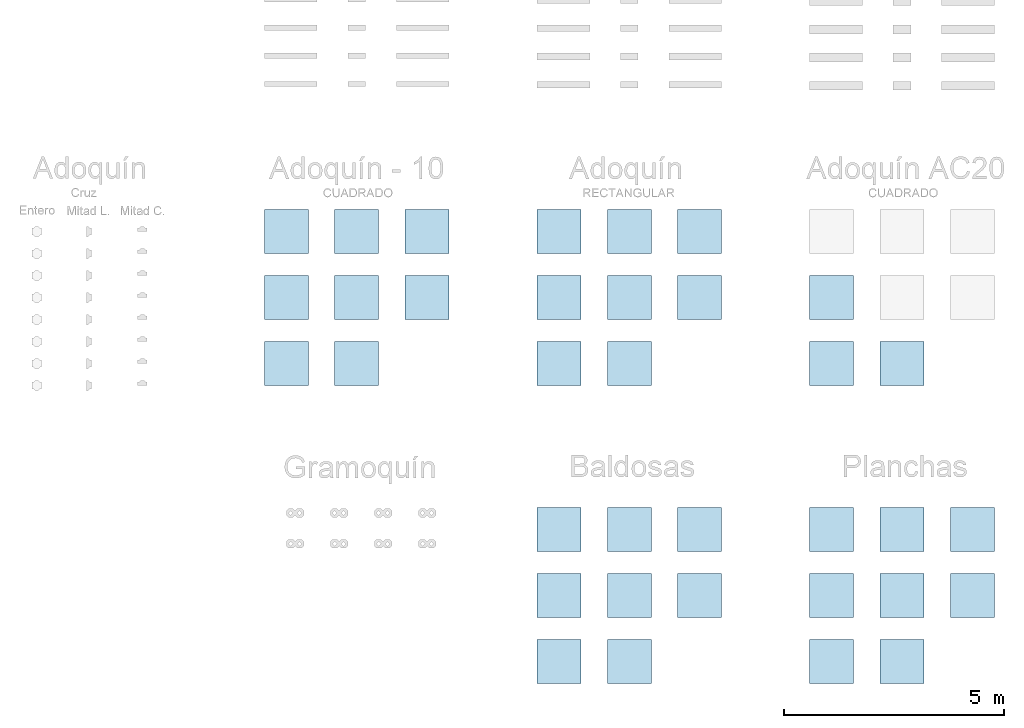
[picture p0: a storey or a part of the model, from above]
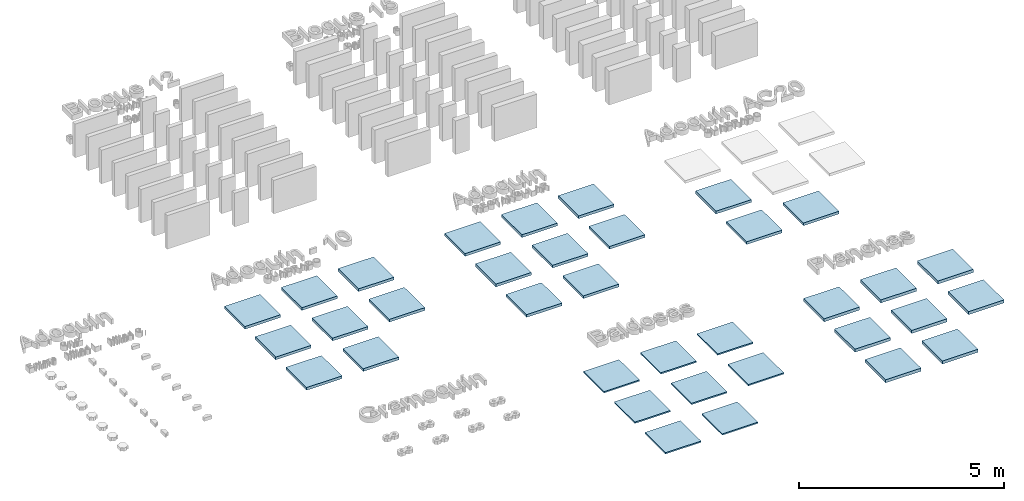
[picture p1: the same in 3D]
Properties of the parts of a building model (IFC2X3), part 1 of 2

# File
Description: ViewDefinition [CoordinationView_V2.0]
File name: Versión 1.0
Time: 2025-05-08T22:21:19
Written by: The EXPRESS Data Manager Version 5.02.0100.07 : 28 Aug 2013
Made in: 21.0.0.383 - Exporter 21.0.0.383 - IU alternativa 21.0.0.383
Comment: STEP Physical File produced by: The EXPRESS Data Manager Version 5.02.0100.07 : 28 Aug 2013 * Module: EDMstepFileFactory/EDMstandAlone * Creation date: Thu May 08 22:21:19 2025 * Host: MSI * Database: C:\Users\valem\AppData\Local\Temp\0c03b512-117e-4236-a8f6-5f3e5b4cf95f\990fe244-7826-4991-a4dd-d05e1d44d0d1\ifc * Database version: 5507 * Database creation date: Thu May 08 22:20:00 2025 * Schema: IFC2X3 * Model: DataRepository.ifc * Model creation date: Thu May 08 22:20:00 2025 * Header model: DataRepository.ifc_HeaderModel * Header model creation date: Thu May 08 22:20:00 2025 * EDMuser: sdai-user * EDMgroup: sdai-group * License ID and type: 5605 : Permanent license. Expiry date: * EDMstepFileFactory options: 020000

# IfcProject, Versión 1.0
LongName: Template Arquitectónicos de La Peña; Phase: Prototipo

# IfcSite, Default
RefLatitude: 40, 25, 13, 9643; RefLongitude: -3, -42, -20, -772056; RefElevation: 0 m

# IfcBuilding
Pset_BuildingCommon - NumberOfStoreys: 1

# IfcBuildingStorey: Nivel:Nivel 1, Nivel 1
LongName: Nivel 1; Elevation: 0 m

# IfcBuildingElementProxy: Texto de modelo:Subtítulo (19)
In: Nivel 1
Type - Pset_BuildingElementProxyCommon - Reference: Subtítulo
Type - Pset_QuantityTakeOff - Reference: Subtítulo
Pset_BuildingElementProxyCommon - sets with these values: 2
Pset_ProvisionForVoid - Shape: Undefined; Width: 0.15 m; Depth: 0.15 m
Name (Texto de modelo:Subtítulo:...)
163555
163556
163563 | Pset_ProvisionForVoid - Height: 0.200913 m
163564
163596
163597
163598 | Pset_ProvisionForVoid - Height: 0.200913 m
163599
163653
163654
163657 | Pset_ProvisionForVoid - Height: 0.200913 m
163658
163723
163767
163825
164239
164240
164241 | Pset_ProvisionForVoid - Height: 0.0251141 m
164242 | Pset_ProvisionForVoid - Height: 0.0251141 m

# IfcBuildingElementProxy: Texto de modelo:Título (10)
In: Nivel 1
Type - Pset_BuildingElementProxyCommon - Reference: Título
Type - Pset_QuantityTakeOff - Reference: Título
Pset_BuildingElementProxyCommon - sets with these values: 2
Pset_ProvisionForVoid - Shape: Undefined; Width: 0.15 m; Depth: 0.15 m
Name (Texto de modelo:Título:...) | Height (m)
163554 | 0.502282
163595 | 0.502282
163652 | 0.502282
163708 | 0.368863
163766 | 0.368863
163824 | 0.368863
163875 | 0.368863
164123 | 0.502282
164180 | 0.502282
164230 | 0.368863

# IfcSlab: Gramoquín10:Gramoquín, Gramoquín10:Gramoquín:164282
In: Nivel 1
Type - PredefinedType: FLOOR; Material: Adoquín Cruz - Rojo
Type - Pset_ManufacturerTypeInformation - Manufacturer: Bloques de la Peña
Type - Pset_QuantityTakeOff - Reference: Gramoquín
Type - Pset_ReinforcementBarPitchOfSlab - Reference: Gramoquín
Type - Pset_SlabCommon - IsExternal: no; Reference: Gramoquín
Pset_QuantityTakeOff - sets with these values: 2
Pset_SlabCommon - IsExternal: yes

# IfcSlab: Gramoquín11:Gramoquín, Gramoquín11:Gramoquín:164302
In: Nivel 1
Type - PredefinedType: FLOOR; Material: Adoquín Cruz - Adobe
Type - Pset_ManufacturerTypeInformation - Manufacturer: Bloques de la Peña
Type - Pset_QuantityTakeOff - Reference: Gramoquín
Type - Pset_ReinforcementBarPitchOfSlab - Reference: Gramoquín
Type - Pset_SlabCommon - IsExternal: no; Reference: Gramoquín
Pset_QuantityTakeOff - sets with these values: 2
Pset_SlabCommon - IsExternal: yes

# IfcSlab: Gramoquín12:Gramoquín, Gramoquín12:Gramoquín:164322
In: Nivel 1
Type - PredefinedType: FLOOR; Material: Adoquín Cruz - Amarillo
Type - Pset_ManufacturerTypeInformation - Manufacturer: Bloques de la Peña
Type - Pset_QuantityTakeOff - Reference: Gramoquín
Type - Pset_ReinforcementBarPitchOfSlab - Reference: Gramoquín
Type - Pset_SlabCommon - IsExternal: no; Reference: Gramoquín
Pset_QuantityTakeOff - sets with these values: 2
Pset_SlabCommon - IsExternal: yes

# IfcSlab: Gramoquín13:Gramoquín, Gramoquín13:Gramoquín:164342
In: Nivel 1
Type - PredefinedType: FLOOR; Material: Adoquín Cruz - Gris
Type - Pset_ManufacturerTypeInformation - Manufacturer: Bloques de la Peña
Type - Pset_QuantityTakeOff - Reference: Gramoquín
Type - Pset_ReinforcementBarPitchOfSlab - Reference: Gramoquín
Type - Pset_SlabCommon - IsExternal: no; Reference: Gramoquín
Pset_QuantityTakeOff - sets with these values: 2
Pset_SlabCommon - IsExternal: yes

# IfcSlab: Gramoquín14:Gramoquín, Gramoquín14:Gramoquín:164362
In: Nivel 1
Type - PredefinedType: FLOOR; Material: Adoquín Cruz - Chocolate
Type - Pset_ManufacturerTypeInformation - Manufacturer: Bloques de la Peña
Type - Pset_QuantityTakeOff - Reference: Gramoquín
Type - Pset_ReinforcementBarPitchOfSlab - Reference: Gramoquín
Type - Pset_SlabCommon - IsExternal: no; Reference: Gramoquín
Pset_QuantityTakeOff - sets with these values: 2
Pset_SlabCommon - IsExternal: yes

# IfcSlab: Gramoquín15:Gramoquín, Gramoquín15:Gramoquín:164382
In: Nivel 1
Type - PredefinedType: FLOOR; Material: Adoquín Cruz - Negro
Type - Pset_ManufacturerTypeInformation - Manufacturer: Bloques de la Peña
Type - Pset_QuantityTakeOff - Reference: Gramoquín
Type - Pset_ReinforcementBarPitchOfSlab - Reference: Gramoquín
Type - Pset_SlabCommon - IsExternal: no; Reference: Gramoquín
Pset_QuantityTakeOff - sets with these values: 2
Pset_SlabCommon - IsExternal: yes

# IfcSlab: Gramoquín16:Gramoquín, Gramoquín16:Gramoquín:164402
In: Nivel 1
Type - PredefinedType: FLOOR; Material: Adoquín Cruz - Natural
Type - Pset_ManufacturerTypeInformation - Manufacturer: Bloques de la Peña
Type - Pset_QuantityTakeOff - Reference: Gramoquín
Type - Pset_ReinforcementBarPitchOfSlab - Reference: Gramoquín
Type - Pset_SlabCommon - IsExternal: no; Reference: Gramoquín
Pset_QuantityTakeOff - sets with these values: 2
Pset_SlabCommon - IsExternal: yes

# IfcSlab: Gramoquín17:Gramoquín, Gramoquín17:Gramoquín:164433
In: Nivel 1
Type - PredefinedType: FLOOR; Material: Adoquín Cruz - Rosado
Type - Pset_ManufacturerTypeInformation - Manufacturer: Bloques de la Peña
Type - Pset_QuantityTakeOff - Reference: Gramoquín
Type - Pset_ReinforcementBarPitchOfSlab - Reference: Gramoquín
Type - Pset_SlabCommon - IsExternal: no; Reference: Gramoquín
Pset_QuantityTakeOff - sets with these values: 2
Pset_SlabCommon - IsExternal: yes

# IfcSlab: Gramoquín18:Gramoquín, Gramoquín18:Gramoquín:164449
In: Nivel 1
Type - PredefinedType: FLOOR; Material: Adoquín Cruz - Rojo
Type - Pset_ManufacturerTypeInformation - Manufacturer: Bloques de la Peña
Type - Pset_QuantityTakeOff - Reference: Gramoquín
Type - Pset_ReinforcementBarPitchOfSlab - Reference: Gramoquín
Type - Pset_SlabCommon - IsExternal: no; Reference: Gramoquín
Pset_QuantityTakeOff - sets with these values: 2
Pset_SlabCommon - IsExternal: yes

# IfcSlab: Gramoquín19:Gramoquín, Gramoquín19:Gramoquín:164465
In: Nivel 1
Type - PredefinedType: FLOOR; Material: Adoquín Cruz - Adobe
Type - Pset_ManufacturerTypeInformation - Manufacturer: Bloques de la Peña
Type - Pset_QuantityTakeOff - Reference: Gramoquín
Type - Pset_ReinforcementBarPitchOfSlab - Reference: Gramoquín
Type - Pset_SlabCommon - IsExternal: no; Reference: Gramoquín
Pset_QuantityTakeOff - sets with these values: 2
Pset_SlabCommon - IsExternal: yes

# IfcSlab: Gramoquín1:Gramoquín, Gramoquín1:Gramoquín:163935
In: Nivel 1
Type - PredefinedType: FLOOR; Material: Gramoquín - Rosado
Type - Pset_ManufacturerTypeInformation - Manufacturer: Bloques de la Peña
Type - Pset_QuantityTakeOff - Reference: Gramoquín
Type - Pset_ReinforcementBarPitchOfSlab - Reference: Gramoquín
Type - Pset_SlabCommon - IsExternal: no; Reference: Gramoquín
Pset_QuantityTakeOff - sets with these values: 2
Pset_SlabCommon - IsExternal: yes

# IfcSlab: Gramoquín20:Gramoquín, Gramoquín20:Gramoquín:164481
In: Nivel 1
Type - PredefinedType: FLOOR; Material: Adoquín Cruz - Amarillo
Type - Pset_ManufacturerTypeInformation - Manufacturer: Bloques de la Peña
Type - Pset_QuantityTakeOff - Reference: Gramoquín
Type - Pset_ReinforcementBarPitchOfSlab - Reference: Gramoquín
Type - Pset_SlabCommon - IsExternal: no; Reference: Gramoquín
Pset_QuantityTakeOff - sets with these values: 2
Pset_SlabCommon - IsExternal: yes

# IfcSlab: Gramoquín21:Gramoquín, Gramoquín21:Gramoquín:164497
In: Nivel 1
Type - PredefinedType: FLOOR; Material: Adoquín Cruz - Gris
Type - Pset_ManufacturerTypeInformation - Manufacturer: Bloques de la Peña
Type - Pset_QuantityTakeOff - Reference: Gramoquín
Type - Pset_ReinforcementBarPitchOfSlab - Reference: Gramoquín
Type - Pset_SlabCommon - IsExternal: no; Reference: Gramoquín
Pset_QuantityTakeOff - sets with these values: 2
Pset_SlabCommon - IsExternal: yes

# IfcSlab: Gramoquín22:Gramoquín, Gramoquín22:Gramoquín:164513
In: Nivel 1
Type - PredefinedType: FLOOR; Material: Adoquín Cruz - Chocolate
Type - Pset_ManufacturerTypeInformation - Manufacturer: Bloques de la Peña
Type - Pset_QuantityTakeOff - Reference: Gramoquín
Type - Pset_ReinforcementBarPitchOfSlab - Reference: Gramoquín
Type - Pset_SlabCommon - IsExternal: no; Reference: Gramoquín
Pset_QuantityTakeOff - sets with these values: 2
Pset_SlabCommon - IsExternal: yes

# IfcSlab: Gramoquín23:Gramoquín, Gramoquín23:Gramoquín:164529
In: Nivel 1
Type - PredefinedType: FLOOR; Material: Adoquín Cruz - Negro
Type - Pset_ManufacturerTypeInformation - Manufacturer: Bloques de la Peña
Type - Pset_QuantityTakeOff - Reference: Gramoquín
Type - Pset_ReinforcementBarPitchOfSlab - Reference: Gramoquín
Type - Pset_SlabCommon - IsExternal: no; Reference: Gramoquín
Pset_QuantityTakeOff - sets with these values: 2
Pset_SlabCommon - IsExternal: yes

# IfcSlab: Gramoquín24:Gramoquín, Gramoquín24:Gramoquín:164417
In: Nivel 1
Type - PredefinedType: FLOOR; Material: Adoquín Cruz - Natural
Type - Pset_ManufacturerTypeInformation - Manufacturer: Bloques de la Peña
Type - Pset_QuantityTakeOff - Reference: Gramoquín
Type - Pset_ReinforcementBarPitchOfSlab - Reference: Gramoquín
Type - Pset_SlabCommon - IsExternal: no; Reference: Gramoquín
Pset_QuantityTakeOff - sets with these values: 2
Pset_SlabCommon - IsExternal: yes

# IfcSlab: Gramoquín25:Gramoquín, Gramoquín25:Gramoquín:164546
In: Nivel 1
Type - PredefinedType: FLOOR; Material: Adoquín Cruz - Rosado
Type - Pset_ManufacturerTypeInformation - Manufacturer: Bloques de la Peña
Type - Pset_QuantityTakeOff - Reference: Gramoquín
Type - Pset_ReinforcementBarPitchOfSlab - Reference: Gramoquín
Type - Pset_SlabCommon - IsExternal: no; Reference: Gramoquín
Pset_QuantityTakeOff - sets with these values: 2
Pset_SlabCommon - IsExternal: yes

# IfcSlab: Gramoquín26:Gramoquín, Gramoquín26:Gramoquín:164562
In: Nivel 1
Type - PredefinedType: FLOOR; Material: Adoquín Cruz - Rojo
Type - Pset_ManufacturerTypeInformation - Manufacturer: Bloques de la Peña
Type - Pset_QuantityTakeOff - Reference: Gramoquín
Type - Pset_ReinforcementBarPitchOfSlab - Reference: Gramoquín
Type - Pset_SlabCommon - IsExternal: no; Reference: Gramoquín
Pset_QuantityTakeOff - sets with these values: 2
Pset_SlabCommon - IsExternal: yes

# IfcSlab: Gramoquín27:Gramoquín, Gramoquín27:Gramoquín:164578
In: Nivel 1
Type - PredefinedType: FLOOR; Material: Adoquín Cruz - Adobe
Type - Pset_ManufacturerTypeInformation - Manufacturer: Bloques de la Peña
Type - Pset_QuantityTakeOff - Reference: Gramoquín
Type - Pset_ReinforcementBarPitchOfSlab - Reference: Gramoquín
Type - Pset_SlabCommon - IsExternal: no; Reference: Gramoquín
Pset_QuantityTakeOff - sets with these values: 2
Pset_SlabCommon - IsExternal: yes

# IfcSlab: Gramoquín28:Gramoquín, Gramoquín28:Gramoquín:164594
In: Nivel 1
Type - PredefinedType: FLOOR; Material: Adoquín Cruz - Amarillo
Type - Pset_ManufacturerTypeInformation - Manufacturer: Bloques de la Peña
Type - Pset_QuantityTakeOff - Reference: Gramoquín
Type - Pset_ReinforcementBarPitchOfSlab - Reference: Gramoquín
Type - Pset_SlabCommon - IsExternal: no; Reference: Gramoquín
Pset_QuantityTakeOff - sets with these values: 2
Pset_SlabCommon - IsExternal: yes

# IfcSlab: Gramoquín29:Gramoquín, Gramoquín29:Gramoquín:164610
In: Nivel 1
Type - PredefinedType: FLOOR; Material: Adoquín Cruz - Gris
Type - Pset_ManufacturerTypeInformation - Manufacturer: Bloques de la Peña
Type - Pset_QuantityTakeOff - Reference: Gramoquín
Type - Pset_ReinforcementBarPitchOfSlab - Reference: Gramoquín
Type - Pset_SlabCommon - IsExternal: no; Reference: Gramoquín
Pset_QuantityTakeOff - sets with these values: 2
Pset_SlabCommon - IsExternal: yes

# IfcSlab: Gramoquín2:Gramoquín, Gramoquín2:Gramoquín:163965
In: Nivel 1
Type - PredefinedType: FLOOR; Material: Gramoquín - Rojo
Type - Pset_ManufacturerTypeInformation - Manufacturer: Bloques de la Peña
Type - Pset_QuantityTakeOff - Reference: Gramoquín
Type - Pset_ReinforcementBarPitchOfSlab - Reference: Gramoquín
Type - Pset_SlabCommon - IsExternal: no; Reference: Gramoquín
Pset_QuantityTakeOff - sets with these values: 2
Pset_SlabCommon - IsExternal: yes

# IfcSlab: Gramoquín30:Gramoquín, Gramoquín30:Gramoquín:164626
In: Nivel 1
Type - PredefinedType: FLOOR; Material: Adoquín Cruz - Chocolate
Type - Pset_ManufacturerTypeInformation - Manufacturer: Bloques de la Peña
Type - Pset_QuantityTakeOff - Reference: Gramoquín
Type - Pset_ReinforcementBarPitchOfSlab - Reference: Gramoquín
Type - Pset_SlabCommon - IsExternal: no; Reference: Gramoquín
Pset_QuantityTakeOff - sets with these values: 2
Pset_SlabCommon - IsExternal: yes

# IfcSlab: Gramoquín31:Gramoquín, Gramoquín31:Gramoquín:164642
In: Nivel 1
Type - PredefinedType: FLOOR; Material: Adoquín Cruz - Negro
Type - Pset_ManufacturerTypeInformation - Manufacturer: Bloques de la Peña
Type - Pset_QuantityTakeOff - Reference: Gramoquín
Type - Pset_ReinforcementBarPitchOfSlab - Reference: Gramoquín
Type - Pset_SlabCommon - IsExternal: no; Reference: Gramoquín
Pset_QuantityTakeOff - sets with these values: 2
Pset_SlabCommon - IsExternal: yes

# IfcSlab: Gramoquín3:Gramoquín, Gramoquín3:Gramoquín:163995
In: Nivel 1
Type - PredefinedType: FLOOR; Material: Gramoquín - Adobe
Type - Pset_ManufacturerTypeInformation - Manufacturer: Bloques de la Peña
Type - Pset_QuantityTakeOff - Reference: Gramoquín
Type - Pset_ReinforcementBarPitchOfSlab - Reference: Gramoquín
Type - Pset_SlabCommon - IsExternal: no; Reference: Gramoquín
Pset_QuantityTakeOff - sets with these values: 2
Pset_SlabCommon - IsExternal: yes

# IfcSlab: Gramoquín4:Gramoquín, Gramoquín4:Gramoquín:164025
In: Nivel 1
Type - PredefinedType: FLOOR; Material: Gramoquín - Amarillo
Type - Pset_ManufacturerTypeInformation - Manufacturer: Bloques de la Peña
Type - Pset_QuantityTakeOff - Reference: Gramoquín
Type - Pset_ReinforcementBarPitchOfSlab - Reference: Gramoquín
Type - Pset_SlabCommon - IsExternal: no; Reference: Gramoquín
Pset_QuantityTakeOff - sets with these values: 2
Pset_SlabCommon - IsExternal: yes

# IfcSlab: Gramoquín5:Gramoquín, Gramoquín5:Gramoquín:164055
In: Nivel 1
Type - PredefinedType: FLOOR; Material: Gramoquín - Gris
Type - Pset_ManufacturerTypeInformation - Manufacturer: Bloques de la Peña
Type - Pset_QuantityTakeOff - Reference: Gramoquín
Type - Pset_ReinforcementBarPitchOfSlab - Reference: Gramoquín
Type - Pset_SlabCommon - IsExternal: no; Reference: Gramoquín
Pset_QuantityTakeOff - sets with these values: 2
Pset_SlabCommon - IsExternal: yes

# IfcSlab: Gramoquín6:Gramoquín, Gramoquín6:Gramoquín:164085
In: Nivel 1
Type - PredefinedType: FLOOR; Material: Gramoquín - Chocolate
Type - Pset_ManufacturerTypeInformation - Manufacturer: Bloques de la Peña
Type - Pset_QuantityTakeOff - Reference: Gramoquín
Type - Pset_ReinforcementBarPitchOfSlab - Reference: Gramoquín
Type - Pset_SlabCommon - IsExternal: no; Reference: Gramoquín
Pset_QuantityTakeOff - sets with these values: 2
Pset_SlabCommon - IsExternal: yes

# IfcSlab: Gramoquín7:Gramoquín, Gramoquín7:Gramoquín:164115
In: Nivel 1
Type - PredefinedType: FLOOR; Material: Gramoquín - Negro
Type - Pset_ManufacturerTypeInformation - Manufacturer: Bloques de la Peña
Type - Pset_QuantityTakeOff - Reference: Gramoquín
Type - Pset_ReinforcementBarPitchOfSlab - Reference: Gramoquín
Type - Pset_SlabCommon - IsExternal: no; Reference: Gramoquín
Pset_QuantityTakeOff - sets with these values: 2
Pset_SlabCommon - IsExternal: yes

# IfcSlab: Gramoquín8:Gramoquín, Gramoquín8:Gramoquín:164238
In: Nivel 1
Type - PredefinedType: FLOOR; Material: Adoquín Cruz - Natural
Type - Pset_ManufacturerTypeInformation - Manufacturer: Bloques de la Peña
Type - Pset_QuantityTakeOff - Reference: Gramoquín
Type - Pset_ReinforcementBarPitchOfSlab - Reference: Gramoquín
Type - Pset_SlabCommon - IsExternal: no; Reference: Gramoquín
Pset_QuantityTakeOff - sets with these values: 2
Pset_SlabCommon - IsExternal: yes

# IfcSlab: Gramoquín9:Gramoquín, Gramoquín9:Gramoquín:164262
In: Nivel 1
Type - PredefinedType: FLOOR; Material: Adoquín Cruz - Rosado
Type - Pset_ManufacturerTypeInformation - Manufacturer: Bloques de la Peña
Type - Pset_QuantityTakeOff - Reference: Gramoquín
Type - Pset_ReinforcementBarPitchOfSlab - Reference: Gramoquín
Type - Pset_SlabCommon - IsExternal: no; Reference: Gramoquín
Pset_QuantityTakeOff - sets with these values: 2
Pset_SlabCommon - IsExternal: yes

# IfcSlab: Gramoquín:Gramoquín, Gramoquín:Gramoquín:163905
In: Nivel 1
Type - PredefinedType: FLOOR; Material: Gramoquín - Natural
Type - Pset_ManufacturerTypeInformation - Manufacturer: Bloques de la Peña
Type - Pset_QuantityTakeOff - Reference: Gramoquín
Type - Pset_ReinforcementBarPitchOfSlab - Reference: Gramoquín
Type - Pset_SlabCommon - IsExternal: no; Reference: Gramoquín
Pset_QuantityTakeOff - sets with these values: 2
Pset_SlabCommon - IsExternal: yes

# IfcSlab: Suelo:Adoquín (Rectangular) - Adobe, Suelo:Adoquín (Rectangular) - Adobe:163784
In: Nivel 1
Type - PredefinedType: FLOOR; Material: Adoquín (Rectangular) - Adobe 0.08 m
Type - Pset_ManufacturerTypeInformation - Manufacturer: Bloques de la Peña
Type - Pset_QuantityTakeOff - Reference: Adoquín (Rectangular) - Adobe
Type - Pset_ReinforcementBarPitchOfSlab - Reference: Adoquín (Rectangular) - Adobe
Type - Pset_SlabCommon - IsExternal: no; Reference: Adoquín (Rectangular) - Adobe
Pset_QuantityTakeOff - sets with these values: 2
Pset_SlabCommon - LoadBearing: no; PitchAngle: 0 deg

# IfcSlab: Suelo:Adoquín (Rectangular) - Amarillo, Suelo:Adoquín (Rectangular) - Amarillo:163791
In: Nivel 1
Type - PredefinedType: FLOOR; Material: Adoquín (Rectangular) - Amarillo 0.08 m
Type - Pset_ManufacturerTypeInformation - Manufacturer: Bloques de la Peña
Type - Pset_QuantityTakeOff - Reference: Adoquín (Rectangular) - Amarillo
Type - Pset_ReinforcementBarPitchOfSlab - Reference: Adoquín (Rectangular) - Amarillo
Type - Pset_SlabCommon - IsExternal: no; Reference: Adoquín (Rectangular) - Amarillo
Pset_QuantityTakeOff - sets with these values: 2
Pset_SlabCommon - LoadBearing: no; PitchAngle: 0 deg

# IfcSlab: Suelo:Adoquín (Rectangular) - Chocolate, Suelo:Adoquín (Rectangular) - Chocolate:163805
In: Nivel 1
Type - PredefinedType: FLOOR; Material: Adoquín (Rectangular) - Chocolate 0.08 m
Type - Pset_ManufacturerTypeInformation - Manufacturer: Bloques de la Peña
Type - Pset_QuantityTakeOff - Reference: Adoquín (Rectangular) - Chocolate
Type - Pset_ReinforcementBarPitchOfSlab - Reference: Adoquín (Rectangular) - Chocolate
Type - Pset_SlabCommon - IsExternal: no; Reference: Adoquín (Rectangular) - Chocolate
Pset_QuantityTakeOff - sets with these values: 2
Pset_SlabCommon - LoadBearing: no; PitchAngle: 0 deg

# IfcSlab: Suelo:Adoquín (Rectangular) - Gris, Suelo:Adoquín (Rectangular) - Gris:163798
In: Nivel 1
Type - PredefinedType: FLOOR; Material: Adoquín (Rectangular) - Gris 0.08 m
Type - Pset_ManufacturerTypeInformation - Manufacturer: Bloques de la Peña
Type - Pset_QuantityTakeOff - Reference: Adoquín (Rectangular) - Gris
Type - Pset_ReinforcementBarPitchOfSlab - Reference: Adoquín (Rectangular) - Gris
Type - Pset_SlabCommon - IsExternal: no; Reference: Adoquín (Rectangular) - Gris
Pset_QuantityTakeOff - sets with these values: 2
Pset_SlabCommon - LoadBearing: no; PitchAngle: 0 deg

# IfcSlab: Suelo:Adoquín (Rectangular) - Natural, Suelo:Adoquín (Rectangular) - Natural:163761
In: Nivel 1
Type - PredefinedType: FLOOR; Material: Adoquín (Rectangular) - Natural 0.08 m
Type - Pset_ManufacturerTypeInformation - Manufacturer: Bloques de la Peña
Type - Pset_QuantityTakeOff - Reference: Adoquín (Rectangular) - Natural
Type - Pset_ReinforcementBarPitchOfSlab - Reference: Adoquín (Rectangular) - Natural
Type - Pset_SlabCommon - IsExternal: no; Reference: Adoquín (Rectangular) - Natural
Pset_QuantityTakeOff - sets with these values: 2
Pset_SlabCommon - LoadBearing: no; PitchAngle: 0 deg

# IfcSlab: Suelo:Adoquín (Rectangular) - Negro, Suelo:Adoquín (Rectangular) - Negro:163812
In: Nivel 1
Type - PredefinedType: FLOOR; Material: Adoquín (Rectangular) - Negro 0.08 m
Type - Pset_ManufacturerTypeInformation - Manufacturer: Bloques de la Peña
Type - Pset_QuantityTakeOff - Reference: Adoquín (Rectangular) - Negro
Type - Pset_ReinforcementBarPitchOfSlab - Reference: Adoquín (Rectangular) - Negro
Type - Pset_SlabCommon - IsExternal: no; Reference: Adoquín (Rectangular) - Negro
Pset_QuantityTakeOff - sets with these values: 2
Pset_SlabCommon - LoadBearing: no; PitchAngle: 0 deg

# IfcSlab: Suelo:Adoquín (Rectangular) - Rojo, Suelo:Adoquín (Rectangular) - Rojo:163777
In: Nivel 1
Type - PredefinedType: FLOOR; Material: Adoquín (Rectangular) - Rojo 0.08 m
Type - Pset_ManufacturerTypeInformation - Manufacturer: Bloques de la Peña
Type - Pset_QuantityTakeOff - Reference: Adoquín (Rectangular) - Rojo
Type - Pset_ReinforcementBarPitchOfSlab - Reference: Adoquín (Rectangular) - Rojo
Type - Pset_SlabCommon - IsExternal: no; Reference: Adoquín (Rectangular) - Rojo
Pset_QuantityTakeOff - sets with these values: 2
Pset_SlabCommon - LoadBearing: no; PitchAngle: 0 deg

# IfcSlab: Suelo:Adoquín (Rectangular) - Rosado, Suelo:Adoquín (Rectangular) - Rosado:163770
In: Nivel 1
Type - PredefinedType: FLOOR; Material: Adoquín (Rectangular) - Rosado 0.08 m
Type - Pset_ManufacturerTypeInformation - Manufacturer: Bloques de la Peña
Type - Pset_QuantityTakeOff - Reference: Adoquín (Rectangular) - Rosado
Type - Pset_ReinforcementBarPitchOfSlab - Reference: Adoquín (Rectangular) - Rosado
Type - Pset_SlabCommon - IsExternal: no; Reference: Adoquín (Rectangular) - Rosado
Pset_QuantityTakeOff - sets with these values: 2
Pset_SlabCommon - LoadBearing: no; PitchAngle: 0 deg

# IfcSlab: Suelo:Adoquín 10 - Adobe, Suelo:Adoquín 10 - Adobe:163726
In: Nivel 1
Type - PredefinedType: FLOOR; Material: Adoquín (10) - Adobe 0.08 m
Type - Pset_ManufacturerTypeInformation - Manufacturer: Bloques de la Peña
Type - Pset_QuantityTakeOff - Reference: Adoquín 10 - Adobe
Type - Pset_ReinforcementBarPitchOfSlab - Reference: Adoquín 10 - Adobe
Type - Pset_SlabCommon - IsExternal: no; Reference: Adoquín 10 - Adobe
Pset_QuantityTakeOff - sets with these values: 2
Pset_SlabCommon - LoadBearing: no; PitchAngle: 0 deg

# IfcSlab: Suelo:Adoquín 10 - Amarillo, Suelo:Adoquín 10 - Amarillo:163740
In: Nivel 1
Type - PredefinedType: FLOOR; Material: Adoquín (10) - Amarillo 0.08 m
Type - Pset_ManufacturerTypeInformation - Manufacturer: Bloques de la Peña
Type - Pset_QuantityTakeOff - Reference: Adoquín 10 - Amarillo
Type - Pset_ReinforcementBarPitchOfSlab - Reference: Adoquín 10 - Amarillo
Type - Pset_SlabCommon - IsExternal: no; Reference: Adoquín 10 - Amarillo
Pset_QuantityTakeOff - sets with these values: 2
Pset_SlabCommon - LoadBearing: no; PitchAngle: 0 deg

# IfcSlab: Suelo:Adoquín 10 - Chocolate, Suelo:Adoquín 10 - Chocolate:163747
In: Nivel 1
Type - PredefinedType: FLOOR; Material: Adoquín (10) - Chocolate 0.08 m
Type - Pset_ManufacturerTypeInformation - Manufacturer: Bloques de la Peña
Type - Pset_QuantityTakeOff - Reference: Adoquín 10 - Chocolate
Type - Pset_ReinforcementBarPitchOfSlab - Reference: Adoquín 10 - Chocolate
Type - Pset_SlabCommon - IsExternal: no; Reference: Adoquín 10 - Chocolate
Pset_QuantityTakeOff - sets with these values: 2
Pset_SlabCommon - LoadBearing: no; PitchAngle: 0 deg

# IfcSlab: Suelo:Adoquín 10 - Gris, Suelo:Adoquín 10 - Gris:163733
In: Nivel 1
Type - PredefinedType: FLOOR; Material: Adoquín (10) - Gris 0.08 m
Type - Pset_ManufacturerTypeInformation - Manufacturer: Bloques de la Peña
Type - Pset_QuantityTakeOff - Reference: Adoquín 10 - Gris
Type - Pset_ReinforcementBarPitchOfSlab - Reference: Adoquín 10 - Gris
Type - Pset_SlabCommon - IsExternal: no; Reference: Adoquín 10 - Gris
Pset_QuantityTakeOff - sets with these values: 2
Pset_SlabCommon - LoadBearing: no; PitchAngle: 0 deg

# IfcSlab: Suelo:Adoquín 10 - Natural, Suelo:Adoquín 10 - Natural:163703
In: Nivel 1
Type - PredefinedType: FLOOR; Material: Adoquín (10) - Natural 0.08 m
Type - Pset_ManufacturerTypeInformation - Manufacturer: Bloques de la Peña
Type - Pset_QuantityTakeOff - Reference: Adoquín 10 - Natural
Type - Pset_ReinforcementBarPitchOfSlab - Reference: Adoquín 10 - Natural
Type - Pset_SlabCommon - IsExternal: no; Reference: Adoquín 10 - Natural
Pset_QuantityTakeOff - sets with these values: 2
Pset_SlabCommon - LoadBearing: no; PitchAngle: 0 deg

# IfcSlab: Suelo:Adoquín 10 - Negro, Suelo:Adoquín 10 - Negro:163754
In: Nivel 1
Type - PredefinedType: FLOOR; Material: Adoquín (10) - Negro 0.08 m
Type - Pset_ManufacturerTypeInformation - Manufacturer: Bloques de la Peña
Type - Pset_QuantityTakeOff - Reference: Adoquín 10 - Negro
Type - Pset_ReinforcementBarPitchOfSlab - Reference: Adoquín 10 - Negro
Type - Pset_SlabCommon - IsExternal: no; Reference: Adoquín 10 - Negro
Pset_QuantityTakeOff - sets with these values: 2
Pset_SlabCommon - LoadBearing: no; PitchAngle: 0 deg

# IfcSlab: Suelo:Adoquín 10 - Rojo, Suelo:Adoquín 10 - Rojo:163711
In: Nivel 1
Type - PredefinedType: FLOOR; Material: Adoquín (10) - Rojo 0.08 m
Type - Pset_ManufacturerTypeInformation - Manufacturer: Bloques de la Peña
Type - Pset_QuantityTakeOff - Reference: Adoquín 10 - Rojo
Type - Pset_ReinforcementBarPitchOfSlab - Reference: Adoquín 10 - Rojo
Type - Pset_SlabCommon - IsExternal: no; Reference: Adoquín 10 - Rojo
Pset_QuantityTakeOff - sets with these values: 2
Pset_SlabCommon - LoadBearing: no; PitchAngle: 0 deg

# IfcSlab: Suelo:Adoquín 10 - Rosado, Suelo:Adoquín 10 - Rosado:163718
In: Nivel 1
Type - PredefinedType: FLOOR; Material: Adoquín (10) - Rosado 0.08 m
Type - Pset_ManufacturerTypeInformation - Manufacturer: Bloques de la Peña
Type - Pset_QuantityTakeOff - Reference: Adoquín 10 - Rosado
Type - Pset_ReinforcementBarPitchOfSlab - Reference: Adoquín 10 - Rosado
Type - Pset_SlabCommon - IsExternal: no; Reference: Adoquín 10 - Rosado
Pset_QuantityTakeOff - sets with these values: 2
Pset_SlabCommon - LoadBearing: no; PitchAngle: 0 deg

# IfcSlab: Suelo:Adoquín AC20 - Adobe, Suelo:Adoquín AC20 - Adobe:163842
In: Nivel 1
Type - PredefinedType: FLOOR; Material: Adoquín AC20 - Adobe 0.08 m
Type - Pset_ManufacturerTypeInformation - Manufacturer: Bloques de la Peña
Type - Pset_QuantityTakeOff - Reference: Adoquín AC20 - Adobe
Type - Pset_ReinforcementBarPitchOfSlab - Reference: Adoquín AC20 - Adobe
Type - Pset_SlabCommon - IsExternal: no; Reference: Adoquín AC20 - Adobe
Pset_QuantityTakeOff - sets with these values: 2
Pset_SlabCommon - LoadBearing: no; PitchAngle: 0 deg

# IfcSlab: Suelo:Adoquín AC20 - Amarillo, Suelo:Adoquín AC20 - Amarillo:163849
In: Nivel 1
Type - PredefinedType: FLOOR; Material: Adoquín AC20 - Amarillo 0.08 m
Type - Pset_ManufacturerTypeInformation - Manufacturer: Bloques de la Peña
Type - Pset_QuantityTakeOff - Reference: Adoquín AC20 - Amarillo
Type - Pset_ReinforcementBarPitchOfSlab - Reference: Adoquín AC20 - Amarillo
Type - Pset_SlabCommon - IsExternal: no; Reference: Adoquín AC20 - Amarillo
Pset_QuantityTakeOff - sets with these values: 2
Pset_SlabCommon - LoadBearing: no; PitchAngle: 0 deg

# IfcSlab: Suelo:Adoquín AC20 - Chocolate, Suelo:Adoquín AC20 - Chocolate:163863
In: Nivel 1
Type - PredefinedType: FLOOR; Material: Adoquín AC20 - Chocolate 0.08 m
Type - Pset_ManufacturerTypeInformation - Manufacturer: Bloques de la Peña
Type - Pset_QuantityTakeOff - Reference: Adoquín AC20 - Chocolate
Type - Pset_ReinforcementBarPitchOfSlab - Reference: Adoquín AC20 - Chocolate
Type - Pset_SlabCommon - IsExternal: no; Reference: Adoquín AC20 - Chocolate
Pset_QuantityTakeOff - sets with these values: 2
Pset_SlabCommon - LoadBearing: no; PitchAngle: 0 deg

# IfcSlab: Suelo:Adoquín AC20 - Gris, Suelo:Adoquín AC20 - Gris:163856
In: Nivel 1
Type - PredefinedType: FLOOR; Material: Adoquín AC20 - Gris 0.08 m
Type - Pset_ManufacturerTypeInformation - Manufacturer: Bloques de la Peña
Type - Pset_QuantityTakeOff - Reference: Adoquín AC20 - Gris
Type - Pset_ReinforcementBarPitchOfSlab - Reference: Adoquín AC20 - Gris
Type - Pset_SlabCommon - IsExternal: no; Reference: Adoquín AC20 - Gris
Pset_QuantityTakeOff - sets with these values: 2
Pset_SlabCommon - LoadBearing: no; PitchAngle: 0 deg

# IfcSlab: Suelo:Adoquín AC20 - Natural, Suelo:Adoquín AC20 - Natural:163819
In: Nivel 1
Type - PredefinedType: FLOOR; Material: Adoquín AC20 - Natural 0.08 m
Type - Pset_ManufacturerTypeInformation - Manufacturer: Bloques de la Peña
Type - Pset_QuantityTakeOff - Reference: Adoquín AC20 - Natural
Type - Pset_ReinforcementBarPitchOfSlab - Reference: Adoquín AC20 - Natural
Type - Pset_SlabCommon - IsExternal: no; Reference: Adoquín AC20 - Natural
Pset_QuantityTakeOff - sets with these values: 2
Pset_SlabCommon - LoadBearing: no; PitchAngle: 0 deg

# IfcSlab: Suelo:Adoquín AC20 - Negro, Suelo:Adoquín AC20 - Negro:163870
In: Nivel 1
Type - PredefinedType: FLOOR; Material: Adoquín AC20 - Negro 0.08 m
Type - Pset_ManufacturerTypeInformation - Manufacturer: Bloques de la Peña
Type - Pset_QuantityTakeOff - Reference: Adoquín AC20 - Negro
Type - Pset_ReinforcementBarPitchOfSlab - Reference: Adoquín AC20 - Negro
Type - Pset_SlabCommon - IsExternal: no; Reference: Adoquín AC20 - Negro
Pset_QuantityTakeOff - sets with these values: 2
Pset_SlabCommon - LoadBearing: no; PitchAngle: 0 deg

# IfcSlab: Suelo:Adoquín AC20 - Rojo, Suelo:Adoquín AC20 - Rojo:163835
In: Nivel 1
Type - PredefinedType: FLOOR; Material: Adoquín AC20 - Rojo 0.08 m
Type - Pset_ManufacturerTypeInformation - Manufacturer: Bloques de la Peña
Type - Pset_QuantityTakeOff - Reference: Adoquín AC20 - Rojo
Type - Pset_ReinforcementBarPitchOfSlab - Reference: Adoquín AC20 - Rojo
Type - Pset_SlabCommon - IsExternal: no; Reference: Adoquín AC20 - Rojo
Pset_QuantityTakeOff - sets with these values: 2
Pset_SlabCommon - LoadBearing: no; PitchAngle: 0 deg

# IfcSlab: Suelo:Adoquín AC20 - Rosado, Suelo:Adoquín AC20 - Rosado:163828
In: Nivel 1
Type - PredefinedType: FLOOR; Material: Adoquín AC20 - Rosado 0.08 m
Type - Pset_ManufacturerTypeInformation - Manufacturer: Bloques de la Peña
Type - Pset_QuantityTakeOff - Reference: Adoquín AC20 - Rosado
Type - Pset_ReinforcementBarPitchOfSlab - Reference: Adoquín AC20 - Rosado
Type - Pset_SlabCommon - IsExternal: no; Reference: Adoquín AC20 - Rosado
Pset_QuantityTakeOff - sets with these values: 2
Pset_SlabCommon - LoadBearing: no; PitchAngle: 0 deg

# IfcSlab: Suelo:Baldosas - Adobe, Suelo:Baldosas - Adobe:164140
In: Nivel 1
Type - PredefinedType: FLOOR; Material: Baldosas - Adobe 0.04 m
Type - Pset_ManufacturerTypeInformation - Manufacturer: Bloques de la Peña
Type - Pset_QuantityTakeOff - Reference: Baldosas - Adobe
Type - Pset_ReinforcementBarPitchOfSlab - Reference: Baldosas - Adobe
Type - Pset_SlabCommon - IsExternal: no; Reference: Baldosas - Adobe
Pset_QuantityTakeOff - sets with these values: 2
Pset_SlabCommon - LoadBearing: no; PitchAngle: 0 deg

# IfcSlab: Suelo:Baldosas - Amarillo, Suelo:Baldosas - Amarillo:164147
In: Nivel 1
Type - PredefinedType: FLOOR; Material: Baldosas - Amarillo 0.04 m
Type - Pset_ManufacturerTypeInformation - Manufacturer: Bloques de la Peña
Type - Pset_QuantityTakeOff - Reference: Baldosas - Amarillo
Type - Pset_ReinforcementBarPitchOfSlab - Reference: Baldosas - Amarillo
Type - Pset_SlabCommon - IsExternal: no; Reference: Baldosas - Amarillo
Pset_QuantityTakeOff - sets with these values: 2
Pset_SlabCommon - LoadBearing: no; PitchAngle: 0 deg

# IfcSlab: Suelo:Baldosas - Chocolate, Suelo:Baldosas - Chocolate:164161
In: Nivel 1
Type - PredefinedType: FLOOR; Material: Baldosas - Chocolate 0.04 m
Type - Pset_ManufacturerTypeInformation - Manufacturer: Bloques de la Peña
Type - Pset_QuantityTakeOff - Reference: Baldosas - Chocolate
Type - Pset_ReinforcementBarPitchOfSlab - Reference: Baldosas - Chocolate
Type - Pset_SlabCommon - IsExternal: no; Reference: Baldosas - Chocolate
Pset_QuantityTakeOff - sets with these values: 2
Pset_SlabCommon - LoadBearing: no; PitchAngle: 0 deg

# IfcSlab: Suelo:Baldosas - Gris, Suelo:Baldosas - Gris:164154
In: Nivel 1
Type - PredefinedType: FLOOR; Material: Baldosas - Gris 0.04 m
Type - Pset_ManufacturerTypeInformation - Manufacturer: Bloques de la Peña
Type - Pset_QuantityTakeOff - Reference: Baldosas - Gris
Type - Pset_ReinforcementBarPitchOfSlab - Reference: Baldosas - Gris
Type - Pset_SlabCommon - IsExternal: no; Reference: Baldosas - Gris
Pset_QuantityTakeOff - sets with these values: 2
Pset_SlabCommon - LoadBearing: no; PitchAngle: 0 deg

# IfcSlab: Suelo:Baldosas - Natural, Suelo:Baldosas - Natural:164118
In: Nivel 1
Type - PredefinedType: FLOOR; Material: Baldosas - Natural 0.04 m
Type - Pset_ManufacturerTypeInformation - Manufacturer: Bloques de la Peña
Type - Pset_QuantityTakeOff - Reference: Baldosas - Natural
Type - Pset_ReinforcementBarPitchOfSlab - Reference: Baldosas - Natural
Type - Pset_SlabCommon - IsExternal: no; Reference: Baldosas - Natural
Pset_QuantityTakeOff - sets with these values: 2
Pset_SlabCommon - LoadBearing: no; PitchAngle: 0 deg

# IfcSlab: Suelo:Baldosas - Negro, Suelo:Baldosas - Negro:164168
In: Nivel 1
Type - PredefinedType: FLOOR; Material: Baldosas - Negro 0.04 m
Type - Pset_ManufacturerTypeInformation - Manufacturer: Bloques de la Peña
Type - Pset_QuantityTakeOff - Reference: Baldosas - Negro
Type - Pset_ReinforcementBarPitchOfSlab - Reference: Baldosas - Negro
Type - Pset_SlabCommon - IsExternal: no; Reference: Baldosas - Negro
Pset_QuantityTakeOff - sets with these values: 2
Pset_SlabCommon - LoadBearing: no; PitchAngle: 0 deg

# IfcSlab: Suelo:Baldosas - Rojo, Suelo:Baldosas - Rojo:164133
In: Nivel 1
Type - PredefinedType: FLOOR; Material: Baldosas - Rojo 0.04 m
Type - Pset_ManufacturerTypeInformation - Manufacturer: Bloques de la Peña
Type - Pset_QuantityTakeOff - Reference: Baldosas - Rojo
Type - Pset_ReinforcementBarPitchOfSlab - Reference: Baldosas - Rojo
Type - Pset_SlabCommon - IsExternal: no; Reference: Baldosas - Rojo
Pset_QuantityTakeOff - sets with these values: 2
Pset_SlabCommon - LoadBearing: no; PitchAngle: 0 deg

# IfcSlab: Suelo:Baldosas - Rosado, Suelo:Baldosas - Rosado:164126
In: Nivel 1
Type - PredefinedType: FLOOR; Material: Baldosas - Rosado 0.04 m
Type - Pset_ManufacturerTypeInformation - Manufacturer: Bloques de la Peña
Type - Pset_QuantityTakeOff - Reference: Baldosas - Rosado
Type - Pset_ReinforcementBarPitchOfSlab - Reference: Baldosas - Rosado
Type - Pset_SlabCommon - IsExternal: no; Reference: Baldosas - Rosado
Pset_QuantityTakeOff - sets with these values: 2
Pset_SlabCommon - LoadBearing: no; PitchAngle: 0 deg

# IfcSlab: Suelo:Planchas - Adobe, Suelo:Planchas - Adobe:164197
In: Nivel 1
Type - PredefinedType: FLOOR; Material: Plancha - Adobe 0.09 m
Type - Pset_ManufacturerTypeInformation - Manufacturer: Bloques de la Peña
Type - Pset_QuantityTakeOff - Reference: Planchas - Adobe
Type - Pset_ReinforcementBarPitchOfSlab - Reference: Planchas - Adobe
Type - Pset_SlabCommon - IsExternal: no; Reference: Planchas - Adobe
Pset_QuantityTakeOff - sets with these values: 2
Pset_SlabCommon - LoadBearing: no; PitchAngle: 0 deg

# IfcSlab: Suelo:Planchas - Amarillo, Suelo:Planchas - Amarillo:164204
In: Nivel 1
Type - PredefinedType: FLOOR; Material: Plancha - Amarillo 0.09 m
Type - Pset_ManufacturerTypeInformation - Manufacturer: Bloques de la Peña
Type - Pset_QuantityTakeOff - Reference: Planchas - Amarillo
Type - Pset_ReinforcementBarPitchOfSlab - Reference: Planchas - Amarillo
Type - Pset_SlabCommon - IsExternal: no; Reference: Planchas - Amarillo
Pset_QuantityTakeOff - sets with these values: 2
Pset_SlabCommon - LoadBearing: no; PitchAngle: 0 deg

# IfcSlab: Suelo:Planchas - Chocolate, Suelo:Planchas - Chocolate:164218
In: Nivel 1
Type - PredefinedType: FLOOR; Material: Plancha - Chocolate 0.09 m
Type - Pset_ManufacturerTypeInformation - Manufacturer: Bloques de la Peña
Type - Pset_QuantityTakeOff - Reference: Planchas - Chocolate
Type - Pset_ReinforcementBarPitchOfSlab - Reference: Planchas - Chocolate
Type - Pset_SlabCommon - IsExternal: no; Reference: Planchas - Chocolate
Pset_QuantityTakeOff - sets with these values: 2
Pset_SlabCommon - LoadBearing: no; PitchAngle: 0 deg

# IfcSlab: Suelo:Planchas - Gris, Suelo:Planchas - Gris:164211
In: Nivel 1
Type - PredefinedType: FLOOR; Material: Plancha - Gris 0.09 m
Type - Pset_ManufacturerTypeInformation - Manufacturer: Bloques de la Peña
Type - Pset_QuantityTakeOff - Reference: Planchas - Gris
Type - Pset_ReinforcementBarPitchOfSlab - Reference: Planchas - Gris
Type - Pset_SlabCommon - IsExternal: no; Reference: Planchas - Gris
Pset_QuantityTakeOff - sets with these values: 2
Pset_SlabCommon - LoadBearing: no; PitchAngle: 0 deg

# IfcSlab: Suelo:Planchas - Natural, Suelo:Planchas - Natural:164175
In: Nivel 1
Type - PredefinedType: FLOOR; Material: Plancha - Natural 0.09 m
Type - Pset_ManufacturerTypeInformation - Manufacturer: Bloques de la Peña
Type - Pset_QuantityTakeOff - Reference: Planchas - Natural
Type - Pset_ReinforcementBarPitchOfSlab - Reference: Planchas - Natural
Type - Pset_SlabCommon - IsExternal: no; Reference: Planchas - Natural
Pset_QuantityTakeOff - sets with these values: 2
Pset_SlabCommon - LoadBearing: no; PitchAngle: 0 deg

# IfcSlab: Suelo:Planchas - Negro, Suelo:Planchas - Negro:164225
In: Nivel 1
Type - PredefinedType: FLOOR; Material: Plancha - Negro 0.09 m
Type - Pset_ManufacturerTypeInformation - Manufacturer: Bloques de la Peña
Type - Pset_QuantityTakeOff - Reference: Planchas - Negro
Type - Pset_ReinforcementBarPitchOfSlab - Reference: Planchas - Negro
Type - Pset_SlabCommon - IsExternal: no; Reference: Planchas - Negro
Pset_QuantityTakeOff - sets with these values: 2
Pset_SlabCommon - LoadBearing: no; PitchAngle: 0 deg

# IfcSlab: Suelo:Planchas - Rojo, Suelo:Planchas - Rojo:164190
In: Nivel 1
Type - PredefinedType: FLOOR; Material: Plancha - Rojo 0.09 m
Type - Pset_ManufacturerTypeInformation - Manufacturer: Bloques de la Peña
Type - Pset_QuantityTakeOff - Reference: Planchas - Rojo
Type - Pset_ReinforcementBarPitchOfSlab - Reference: Planchas - Rojo
Type - Pset_SlabCommon - IsExternal: no; Reference: Planchas - Rojo
Pset_QuantityTakeOff - sets with these values: 2
Pset_SlabCommon - LoadBearing: no; PitchAngle: 0 deg

# IfcSlab: Suelo:Planchas - Rosado, Suelo:Planchas - Rosado:164183
In: Nivel 1
Type - PredefinedType: FLOOR; Material: Plancha - Rosado 0.09 m
Type - Pset_ManufacturerTypeInformation - Manufacturer: Bloques de la Peña
Type - Pset_QuantityTakeOff - Reference: Planchas - Rosado
Type - Pset_ReinforcementBarPitchOfSlab - Reference: Planchas - Rosado
Type - Pset_SlabCommon - IsExternal: no; Reference: Planchas - Rosado
Pset_QuantityTakeOff - sets with these values: 2
Pset_SlabCommon - LoadBearing: no; PitchAngle: 0 deg

# IfcWallStandardCase: Muro básico:Bloque 12 (Dado) / Fachada - Adobe, Muro básico:Bloque 12 (Dado) / Fachada - Adobe:163575
In: Nivel 1
Type - PredefinedType: STANDARD; Material: Bloque (Dado) - Adobe 0.12 m
Type - Pset_ManufacturerTypeInformation - Manufacturer: Bloques de la Peña
Type - Pset_QuantityTakeOff - Reference: Bloque 12 (Dado) / Fachada - Adobe
Type - Pset_ReinforcementBarPitchOfWall - Reference: Bloque 12 (Dado) / Fachada - Adobe
Type - Pset_WallCommon - IsExternal: no; Reference: Bloque 12 (Dado) / Fachada - Adobe
Pset_QuantityTakeOff - sets with these values: 2
Pset_WallCommon - ExtendToStructure: no; LoadBearing: no

# IfcWallStandardCase: Muro básico:Bloque 12 (Dado) / Fachada - Amarillo, Muro básico:Bloque 12 (Dado) / Fachada - Amarillo:163577
In: Nivel 1
Type - PredefinedType: STANDARD; Material: Bloque - Amarillo 0.12 m
Type - Pset_ManufacturerTypeInformation - Manufacturer: Bloques de la Peña
Type - Pset_QuantityTakeOff - Reference: Bloque 12 (Dado) / Fachada - Amarillo
Type - Pset_ReinforcementBarPitchOfWall - Reference: Bloque 12 (Dado) / Fachada - Amarillo
Type - Pset_WallCommon - IsExternal: no; Reference: Bloque 12 (Dado) / Fachada - Amarillo
Pset_QuantityTakeOff - sets with these values: 2
Pset_WallCommon - ExtendToStructure: no; LoadBearing: no

# IfcWallStandardCase: Muro básico:Bloque 12 (Dado) / Fachada - Chocolate, Muro básico:Bloque 12 (Dado) / Fachada - Chocolate:163581
In: Nivel 1
Type - PredefinedType: STANDARD; Material: Bloque (Dado) - Chocolate 0.12 m
Type - Pset_ManufacturerTypeInformation - Manufacturer: Bloques de la Peña
Type - Pset_QuantityTakeOff - Reference: Bloque 12 (Dado) / Fachada - Chocolate
Type - Pset_ReinforcementBarPitchOfWall - Reference: Bloque 12 (Dado) / Fachada - Chocolate
Type - Pset_WallCommon - IsExternal: no; Reference: Bloque 12 (Dado) / Fachada - Chocolate
Pset_QuantityTakeOff - sets with these values: 2
Pset_WallCommon - ExtendToStructure: no; LoadBearing: no

# IfcWallStandardCase: Muro básico:Bloque 12 (Dado) / Fachada - Gris, Muro básico:Bloque 12 (Dado) / Fachada - Gris:163579
In: Nivel 1
Type - PredefinedType: STANDARD; Material: Bloque (Dado) - Gris 0.12 m
Type - Pset_ManufacturerTypeInformation - Manufacturer: Bloques de la Peña
Type - Pset_QuantityTakeOff - Reference: Bloque 12 (Dado) / Fachada - Gris
Type - Pset_ReinforcementBarPitchOfWall - Reference: Bloque 12 (Dado) / Fachada - Gris
Type - Pset_WallCommon - IsExternal: no; Reference: Bloque 12 (Dado) / Fachada - Gris
Pset_QuantityTakeOff - sets with these values: 2
Pset_WallCommon - ExtendToStructure: no; LoadBearing: no

# IfcWallStandardCase: Muro básico:Bloque 12 (Dado) / Fachada - Natural, Muro básico:Bloque 12 (Dado) / Fachada - Natural:163548
In: Nivel 1
Type - PredefinedType: STANDARD; Material: Bloque (Dado) - Natural 0.12 m
Type - Pset_ManufacturerTypeInformation - Manufacturer: Bloques de la Peña
Type - Pset_QuantityTakeOff - Reference: Bloque 12 (Dado) / Fachada - Natural
Type - Pset_ReinforcementBarPitchOfWall - Reference: Bloque 12 (Dado) / Fachada - Natural
Type - Pset_WallCommon - IsExternal: no; Reference: Bloque 12 (Dado) / Fachada - Natural
Pset_QuantityTakeOff - sets with these values: 2
Pset_WallCommon - ExtendToStructure: no; LoadBearing: no

# IfcWallStandardCase: Muro básico:Bloque 12 (Dado) / Fachada - Negro, Muro básico:Bloque 12 (Dado) / Fachada - Negro:163583
In: Nivel 1
Type - PredefinedType: STANDARD; Material: Bloque (Dado) - Negro 0.12 m
Type - Pset_ManufacturerTypeInformation - Manufacturer: Bloques de la Peña
Type - Pset_QuantityTakeOff - Reference: Bloque 12 (Dado) / Fachada - Negro
Type - Pset_ReinforcementBarPitchOfWall - Reference: Bloque 12 (Dado) / Fachada - Negro
Type - Pset_WallCommon - IsExternal: no; Reference: Bloque 12 (Dado) / Fachada - Negro
Pset_QuantityTakeOff - sets with these values: 2
Pset_WallCommon - ExtendToStructure: no; LoadBearing: no

# IfcWallStandardCase: Muro básico:Bloque 12 (Dado) / Fachada - Rojo, Muro básico:Bloque 12 (Dado) / Fachada - Rojo:163552
In: Nivel 1
Type - PredefinedType: STANDARD; Material: Bloque (Dado) - Rojo 0.12 m
Type - Pset_ManufacturerTypeInformation - Manufacturer: Bloques de la Peña
Type - Pset_QuantityTakeOff - Reference: Bloque 12 (Dado) / Fachada - Rojo
Type - Pset_ReinforcementBarPitchOfWall - Reference: Bloque 12 (Dado) / Fachada - Rojo
Type - Pset_WallCommon - IsExternal: no; Reference: Bloque 12 (Dado) / Fachada - Rojo
Pset_QuantityTakeOff - sets with these values: 2
Pset_WallCommon - ExtendToStructure: no; LoadBearing: no

# IfcWallStandardCase: Muro básico:Bloque 12 (Dado) / Fachada - Rosado, Muro básico:Bloque 12 (Dado) / Fachada - Rosado:163550
In: Nivel 1
Type - PredefinedType: STANDARD; Material: Bloque (Dado) - Rosado 0.12 m
Type - Pset_ManufacturerTypeInformation - Manufacturer: Bloques de la Peña
Type - Pset_QuantityTakeOff - Reference: Bloque 12 (Dado) / Fachada - Rosado
Type - Pset_ReinforcementBarPitchOfWall - Reference: Bloque 12 (Dado) / Fachada - Rosado
Type - Pset_WallCommon - IsExternal: no; Reference: Bloque 12 (Dado) / Fachada - Rosado
Pset_QuantityTakeOff - sets with these values: 2
Pset_WallCommon - ExtendToStructure: no; LoadBearing: no

# IfcWallStandardCase: Muro básico:Bloque 12 (Solera) / Fachada - Adobe, Muro básico:Bloque 12 (Solera) / Fachada - Adobe:163585
In: Nivel 1
Type - PredefinedType: STANDARD; Material: Bloque - Adobe 0.12 m
Type - Pset_ManufacturerTypeInformation - Manufacturer: Bloques de la Peña
Type - Pset_QuantityTakeOff - Reference: Bloque 12 (Solera) / Fachada - Adobe
Type - Pset_ReinforcementBarPitchOfWall - Reference: Bloque 12 (Solera) / Fachada - Adobe
Type - Pset_WallCommon - IsExternal: no; Reference: Bloque 12 (Solera) / Fachada - Adobe
Pset_QuantityTakeOff - sets with these values: 2
Pset_WallCommon - ExtendToStructure: no; LoadBearing: no

# IfcWallStandardCase: Muro básico:Bloque 12 (Solera) / Fachada - Amarillo, Muro básico:Bloque 12 (Solera) / Fachada - Amarillo:163587
In: Nivel 1
Type - PredefinedType: STANDARD; Material: Bloque - Amarillo 0.12 m
Type - Pset_ManufacturerTypeInformation - Manufacturer: Bloques de la Peña
Type - Pset_QuantityTakeOff - Reference: Bloque 12 (Solera) / Fachada - Amarillo
Type - Pset_ReinforcementBarPitchOfWall - Reference: Bloque 12 (Solera) / Fachada - Amarillo
Type - Pset_WallCommon - IsExternal: no; Reference: Bloque 12 (Solera) / Fachada - Amarillo
Pset_QuantityTakeOff - sets with these values: 2
Pset_WallCommon - ExtendToStructure: no; LoadBearing: no

# IfcWallStandardCase: Muro básico:Bloque 12 (Solera) / Fachada - Chocolate, Muro básico:Bloque 12 (Solera) / Fachada - Chocolate:163591
In: Nivel 1
Type - PredefinedType: STANDARD; Material: Bloque - Chocolate 0.12 m
Type - Pset_ManufacturerTypeInformation - Manufacturer: Bloques de la Peña
Type - Pset_QuantityTakeOff - Reference: Bloque 12 (Solera) / Fachada - Chocolate
Type - Pset_ReinforcementBarPitchOfWall - Reference: Bloque 12 (Solera) / Fachada - Chocolate
Type - Pset_WallCommon - IsExternal: no; Reference: Bloque 12 (Solera) / Fachada - Chocolate
Pset_QuantityTakeOff - sets with these values: 2
Pset_WallCommon - ExtendToStructure: no; LoadBearing: no

# IfcWallStandardCase: Muro básico:Bloque 12 (Solera) / Fachada - Gris, Muro básico:Bloque 12 (Solera) / Fachada - Gris:163589
In: Nivel 1
Type - PredefinedType: STANDARD; Material: Bloque - Gris 0.12 m
Type - Pset_ManufacturerTypeInformation - Manufacturer: Bloques de la Peña
Type - Pset_QuantityTakeOff - Reference: Bloque 12 (Solera) / Fachada - Gris
Type - Pset_ReinforcementBarPitchOfWall - Reference: Bloque 12 (Solera) / Fachada - Gris
Type - Pset_WallCommon - IsExternal: no; Reference: Bloque 12 (Solera) / Fachada - Gris
Pset_QuantityTakeOff - sets with these values: 2
Pset_WallCommon - ExtendToStructure: no; LoadBearing: no

# IfcWallStandardCase: Muro básico:Bloque 12 (Solera) / Fachada - Natural, Muro básico:Bloque 12 (Solera) / Fachada - Natural:163557
In: Nivel 1
Type - PredefinedType: STANDARD; Material: Bloque - Natural 0.12 m
Type - Pset_ManufacturerTypeInformation - Manufacturer: Bloques de la Peña
Type - Pset_QuantityTakeOff - Reference: Bloque 12 (Solera) / Fachada - Natural
Type - Pset_ReinforcementBarPitchOfWall - Reference: Bloque 12 (Solera) / Fachada - Natural
Type - Pset_WallCommon - IsExternal: no; Reference: Bloque 12 (Solera) / Fachada - Natural
Pset_QuantityTakeOff - sets with these values: 2
Pset_WallCommon - ExtendToStructure: no; LoadBearing: no

# IfcWallStandardCase: Muro básico:Bloque 12 (Solera) / Fachada - Negro, Muro básico:Bloque 12 (Solera) / Fachada - Negro:163593
In: Nivel 1
Type - PredefinedType: STANDARD; Material: Bloque - Negro 0.12 m
Type - Pset_ManufacturerTypeInformation - Manufacturer: Bloques de la Peña
Type - Pset_QuantityTakeOff - Reference: Bloque 12 (Solera) / Fachada - Negro
Type - Pset_ReinforcementBarPitchOfWall - Reference: Bloque 12 (Solera) / Fachada - Negro
Type - Pset_WallCommon - IsExternal: no; Reference: Bloque 12 (Solera) / Fachada - Negro
Pset_QuantityTakeOff - sets with these values: 2
Pset_WallCommon - ExtendToStructure: no; LoadBearing: no

# IfcWallStandardCase: Muro básico:Bloque 12 (Solera) / Fachada - Rojo, Muro básico:Bloque 12 (Solera) / Fachada - Rojo:163561
In: Nivel 1
Type - PredefinedType: STANDARD; Material: Bloque - Rojo 0.12 m
Type - Pset_ManufacturerTypeInformation - Manufacturer: Bloques de la Peña
Type - Pset_QuantityTakeOff - Reference: Bloque 12 (Solera) / Fachada - Rojo
Type - Pset_ReinforcementBarPitchOfWall - Reference: Bloque 12 (Solera) / Fachada - Rojo
Type - Pset_WallCommon - IsExternal: no; Reference: Bloque 12 (Solera) / Fachada - Rojo
Pset_QuantityTakeOff - sets with these values: 2
Pset_WallCommon - ExtendToStructure: no; LoadBearing: no

# IfcWallStandardCase: Muro básico:Bloque 12 (Solera) / Fachada - Rosado, Muro básico:Bloque 12 (Solera) / Fachada - Rosado:163559
In: Nivel 1
Type - PredefinedType: STANDARD; Material: Bloque - Rosado 0.12 m
Type - Pset_ManufacturerTypeInformation - Manufacturer: Bloques de la Peña
Type - Pset_QuantityTakeOff - Reference: Bloque 12 (Solera) / Fachada - Rosado
Type - Pset_ReinforcementBarPitchOfWall - Reference: Bloque 12 (Solera) / Fachada - Rosado
Type - Pset_WallCommon - IsExternal: no; Reference: Bloque 12 (Solera) / Fachada - Rosado
Pset_QuantityTakeOff - sets with these values: 2
Pset_WallCommon - ExtendToStructure: no; LoadBearing: no

# IfcWallStandardCase: Muro básico:Bloque 12 / Fachada - Adobe, Muro básico:Bloque 12 / Fachada - Adobe:163565
In: Nivel 1
Type - PredefinedType: STANDARD; Material: Bloque - Adobe 0.12 m
Type - Pset_ManufacturerTypeInformation - Manufacturer: Bloques de la Peña
Type - Pset_QuantityTakeOff - Reference: Bloque 12 / Fachada - Adobe
Type - Pset_ReinforcementBarPitchOfWall - Reference: Bloque 12 / Fachada - Adobe
Type - Pset_WallCommon - IsExternal: no; Reference: Bloque 12 / Fachada - Adobe
Pset_QuantityTakeOff - sets with these values: 2
Pset_WallCommon - ExtendToStructure: no; LoadBearing: no

# IfcWallStandardCase: Muro básico:Bloque 12 / Fachada - Amarillo, Muro básico:Bloque 12 / Fachada - Amarillo:163567
In: Nivel 1
Type - PredefinedType: STANDARD; Material: Bloque - Amarillo 0.12 m
Type - Pset_ManufacturerTypeInformation - Manufacturer: Bloques de la Peña
Type - Pset_QuantityTakeOff - Reference: Bloque 12 / Fachada - Amarillo
Type - Pset_ReinforcementBarPitchOfWall - Reference: Bloque 12 / Fachada - Amarillo
Type - Pset_WallCommon - IsExternal: no; Reference: Bloque 12 / Fachada - Amarillo
Pset_QuantityTakeOff - sets with these values: 2
Pset_WallCommon - ExtendToStructure: no; LoadBearing: no

# IfcWallStandardCase: Muro básico:Bloque 12 / Fachada - Chocolate, Muro básico:Bloque 12 / Fachada - Chocolate:163571
In: Nivel 1
Type - PredefinedType: STANDARD; Material: Bloque - Chocolate 0.12 m
Type - Pset_ManufacturerTypeInformation - Manufacturer: Bloques de la Peña
Type - Pset_QuantityTakeOff - Reference: Bloque 12 / Fachada - Chocolate
Type - Pset_ReinforcementBarPitchOfWall - Reference: Bloque 12 / Fachada - Chocolate
Type - Pset_WallCommon - IsExternal: no; Reference: Bloque 12 / Fachada - Chocolate
Pset_QuantityTakeOff - sets with these values: 2
Pset_WallCommon - ExtendToStructure: no; LoadBearing: no

# IfcWallStandardCase: Muro básico:Bloque 12 / Fachada - Gris, Muro básico:Bloque 12 / Fachada - Gris:163569
In: Nivel 1
Type - PredefinedType: STANDARD; Material: Bloque - Gris 0.12 m
Type - Pset_ManufacturerTypeInformation - Manufacturer: Bloques de la Peña
Type - Pset_QuantityTakeOff - Reference: Bloque 12 / Fachada - Gris
Type - Pset_ReinforcementBarPitchOfWall - Reference: Bloque 12 / Fachada - Gris
Type - Pset_WallCommon - IsExternal: no; Reference: Bloque 12 / Fachada - Gris
Pset_QuantityTakeOff - sets with these values: 2
Pset_WallCommon - ExtendToStructure: no; LoadBearing: no

# IfcWallStandardCase: Muro básico:Bloque 12 / Fachada - Natural, Muro básico:Bloque 12 / Fachada - Natural:163542
In: Nivel 1
Type - PredefinedType: STANDARD; Material: Bloque - Natural 0.12 m
Type - Pset_ManufacturerTypeInformation - Manufacturer: Bloques de la Peña
Type - Pset_QuantityTakeOff - Reference: Bloque 12 / Fachada - Natural
Type - Pset_ReinforcementBarPitchOfWall - Reference: Bloque 12 / Fachada - Natural
Type - Pset_WallCommon - Reference: Bloque 12 / Fachada - Natural; IsExternal: no
Pset_QuantityTakeOff - sets with these values: 2
Pset_WallCommon - ExtendToStructure: no; LoadBearing: no

# IfcWallStandardCase: Muro básico:Bloque 12 / Fachada - Negro, Muro básico:Bloque 12 / Fachada - Negro:163573
In: Nivel 1
Type - PredefinedType: STANDARD; Material: Bloque - Negro 0.12 m
Type - Pset_ManufacturerTypeInformation - Manufacturer: Bloques de la Peña
Type - Pset_QuantityTakeOff - Reference: Bloque 12 / Fachada - Negro
Type - Pset_ReinforcementBarPitchOfWall - Reference: Bloque 12 / Fachada - Negro
Type - Pset_WallCommon - IsExternal: no; Reference: Bloque 12 / Fachada - Negro
Pset_QuantityTakeOff - sets with these values: 2
Pset_WallCommon - ExtendToStructure: no; LoadBearing: no

# IfcWallStandardCase: Muro básico:Bloque 12 / Fachada - Rojo, Muro básico:Bloque 12 / Fachada - Rojo:163546
In: Nivel 1
Type - PredefinedType: STANDARD; Material: Bloque - Rojo 0.12 m
Type - Pset_ManufacturerTypeInformation - Manufacturer: Bloques de la Peña
Type - Pset_QuantityTakeOff - Reference: Bloque 12 / Fachada - Rojo
Type - Pset_ReinforcementBarPitchOfWall - Reference: Bloque 12 / Fachada - Rojo
Type - Pset_WallCommon - IsExternal: no; Reference: Bloque 12 / Fachada - Rojo
Pset_QuantityTakeOff - sets with these values: 2
Pset_WallCommon - ExtendToStructure: no; LoadBearing: no

# IfcWallStandardCase: Muro básico:Bloque 12 / Fachada - Rosado, Muro básico:Bloque 12 / Fachada - Rosado:163544
In: Nivel 1
Type - PredefinedType: STANDARD; Material: Bloque - Rosado 0.12 m
Type - Pset_ManufacturerTypeInformation - Manufacturer: Bloques de la Peña
Type - Pset_QuantityTakeOff - Reference: Bloque 12 / Fachada - Rosado
Type - Pset_ReinforcementBarPitchOfWall - Reference: Bloque 12 / Fachada - Rosado
Type - Pset_WallCommon - IsExternal: no; Reference: Bloque 12 / Fachada - Rosado
Pset_QuantityTakeOff - sets with these values: 2
Pset_WallCommon - ExtendToStructure: no; LoadBearing: no

# IfcWallStandardCase: Muro básico:Bloque 15 (Dado) / Fachada - Adobe, Muro básico:Bloque 15 (Dado) / Fachada - Adobe:163624
In: Nivel 1
Type - PredefinedType: STANDARD; Material: Bloque (Dado) - Adobe 0.15 m
Type - Pset_ManufacturerTypeInformation - Manufacturer: Bloque de la Peña
Type - Pset_QuantityTakeOff - Reference: Bloque 15 (Dado) / Fachada - Adobe
Type - Pset_ReinforcementBarPitchOfWall - Reference: Bloque 15 (Dado) / Fachada - Adobe
Type - Pset_WallCommon - IsExternal: no; Reference: Bloque 15 (Dado) / Fachada - Adobe
Pset_QuantityTakeOff - sets with these values: 2
Pset_WallCommon - ExtendToStructure: no; LoadBearing: no

# IfcWallStandardCase: Muro básico:Bloque 15 (Dado) / Fachada - Amarillo, Muro básico:Bloque 15 (Dado) / Fachada - Amarillo:163626
In: Nivel 1
Type - PredefinedType: STANDARD; Material: Bloque (Dado) - Amarillo 0.15 m
Type - Pset_ManufacturerTypeInformation - Manufacturer: Bloque de la Peña
Type - Pset_QuantityTakeOff - Reference: Bloque 15 (Dado) / Fachada - Amarillo
Type - Pset_ReinforcementBarPitchOfWall - Reference: Bloque 15 (Dado) / Fachada - Amarillo
Type - Pset_WallCommon - IsExternal: no; Reference: Bloque 15 (Dado) / Fachada - Amarillo
Pset_QuantityTakeOff - sets with these values: 2
Pset_WallCommon - ExtendToStructure: no; LoadBearing: no

# IfcWallStandardCase: Muro básico:Bloque 15 (Dado) / Fachada - Chocolate, Muro básico:Bloque 15 (Dado) / Fachada - Chocolate:163630
In: Nivel 1
Type - PredefinedType: STANDARD; Material: Bloque (Dado) - Chocolate 0.15 m
Type - Pset_ManufacturerTypeInformation - Manufacturer: Bloque de la Peña
Type - Pset_QuantityTakeOff - Reference: Bloque 15 (Dado) / Fachada - Chocolate
Type - Pset_ReinforcementBarPitchOfWall - Reference: Bloque 15 (Dado) / Fachada - Chocolate
Type - Pset_WallCommon - IsExternal: no; Reference: Bloque 15 (Dado) / Fachada - Chocolate
Pset_QuantityTakeOff - sets with these values: 2
Pset_WallCommon - ExtendToStructure: no; LoadBearing: no

# IfcWallStandardCase: Muro básico:Bloque 15 (Dado) / Fachada - Gris, Muro básico:Bloque 15 (Dado) / Fachada - Gris:163628
In: Nivel 1
Type - PredefinedType: STANDARD; Material: Bloque (Dado) - Gris 0.15 m
Type - Pset_ManufacturerTypeInformation - Manufacturer: Bloque de la Peña
Type - Pset_QuantityTakeOff - Reference: Bloque 15 (Dado) / Fachada - Gris
Type - Pset_ReinforcementBarPitchOfWall - Reference: Bloque 15 (Dado) / Fachada - Gris
Type - Pset_WallCommon - IsExternal: no; Reference: Bloque 15 (Dado) / Fachada - Gris
Pset_QuantityTakeOff - sets with these values: 2
Pset_WallCommon - ExtendToStructure: no; LoadBearing: no

# IfcWallStandardCase: Muro básico:Bloque 15 (Dado) / Fachada - Natural, Muro básico:Bloque 15 (Dado) / Fachada - Natural:163602
In: Nivel 1
Type - PredefinedType: STANDARD; Material: Bloque (Dado) - Natural 0.15 m
Type - Pset_ManufacturerTypeInformation - Manufacturer: Bloque de la Peña
Type - Pset_QuantityTakeOff - Reference: Bloque 15 (Dado) / Fachada - Natural
Type - Pset_ReinforcementBarPitchOfWall - Reference: Bloque 15 (Dado) / Fachada - Natural
Type - Pset_WallCommon - IsExternal: no; Reference: Bloque 15 (Dado) / Fachada - Natural
Pset_QuantityTakeOff - sets with these values: 2
Pset_WallCommon - ExtendToStructure: no; LoadBearing: no

# IfcWallStandardCase: Muro básico:Bloque 15 (Dado) / Fachada - Negro, Muro básico:Bloque 15 (Dado) / Fachada - Negro:163632
In: Nivel 1
Type - PredefinedType: STANDARD; Material: Bloque (Dado) - Negro 0.15 m
Type - Pset_ManufacturerTypeInformation - Manufacturer: Bloque de la Peña
Type - Pset_QuantityTakeOff - Reference: Bloque 15 (Dado) / Fachada - Negro
Type - Pset_ReinforcementBarPitchOfWall - Reference: Bloque 15 (Dado) / Fachada - Negro
Type - Pset_WallCommon - IsExternal: no; Reference: Bloque 15 (Dado) / Fachada - Negro
Pset_QuantityTakeOff - sets with these values: 2
Pset_WallCommon - ExtendToStructure: no; LoadBearing: no

# IfcWallStandardCase: Muro básico:Bloque 15 (Dado) / Fachada - Rojo, Muro básico:Bloque 15 (Dado) / Fachada - Rojo:163622
In: Nivel 1
Type - PredefinedType: STANDARD; Material: Bloque (Dado) - Rojo 0.15 m
Type - Pset_ManufacturerTypeInformation - Manufacturer: Bloque de la Peña
Type - Pset_QuantityTakeOff - Reference: Bloque 15 (Dado) / Fachada - Rojo
Type - Pset_ReinforcementBarPitchOfWall - Reference: Bloque 15 (Dado) / Fachada - Rojo
Type - Pset_WallCommon - IsExternal: no; Reference: Bloque 15 (Dado) / Fachada - Rojo
Pset_QuantityTakeOff - sets with these values: 2
Pset_WallCommon - ExtendToStructure: no; LoadBearing: no

# IfcWallStandardCase: Muro básico:Bloque 15 (Dado) / Fachada - Rosado, Muro básico:Bloque 15 (Dado) / Fachada - Rosado:163620
In: Nivel 1
Type - PredefinedType: STANDARD; Material: Bloque (Dado) - Rosado 0.15 m
Type - Pset_ManufacturerTypeInformation - Manufacturer: Bloque de la Peña
Type - Pset_QuantityTakeOff - Reference: Bloque 15 (Dado) / Fachada - Rosado
Type - Pset_ReinforcementBarPitchOfWall - Reference: Bloque 15 (Dado) / Fachada - Rosado
Type - Pset_WallCommon - IsExternal: no; Reference: Bloque 15 (Dado) / Fachada - Rosado
Pset_QuantityTakeOff - sets with these values: 2
Pset_WallCommon - ExtendToStructure: no; LoadBearing: no

# IfcWallStandardCase: Muro básico:Bloque 15 (Solera) / Fachada - Adobe, Muro básico:Bloque 15 (Solera) / Fachada - Adobe:163638
In: Nivel 1
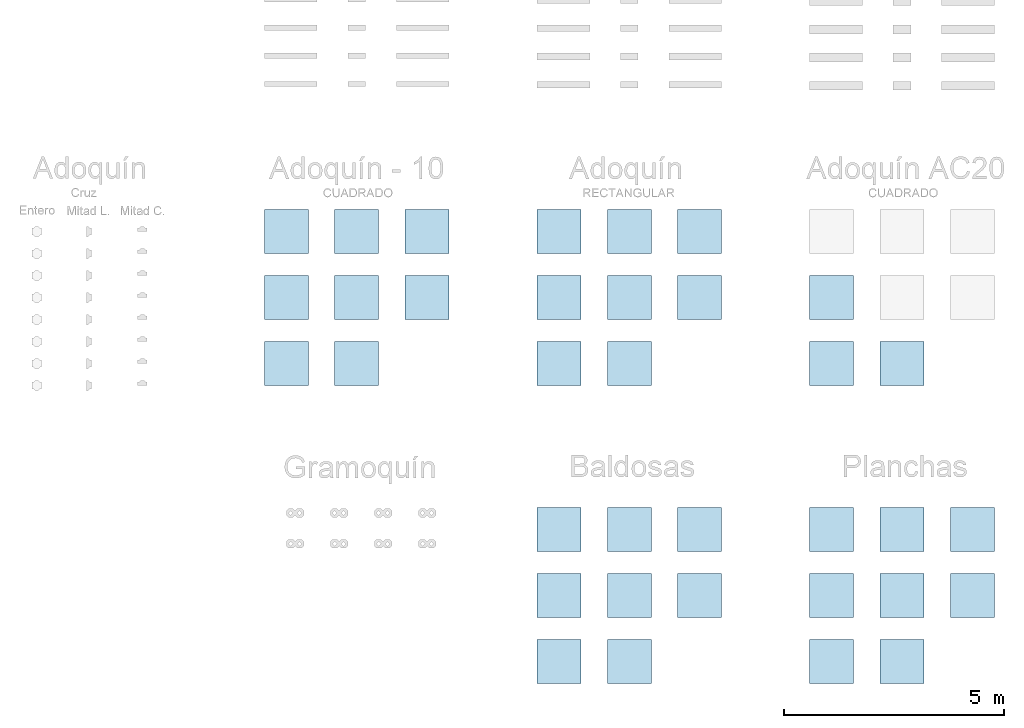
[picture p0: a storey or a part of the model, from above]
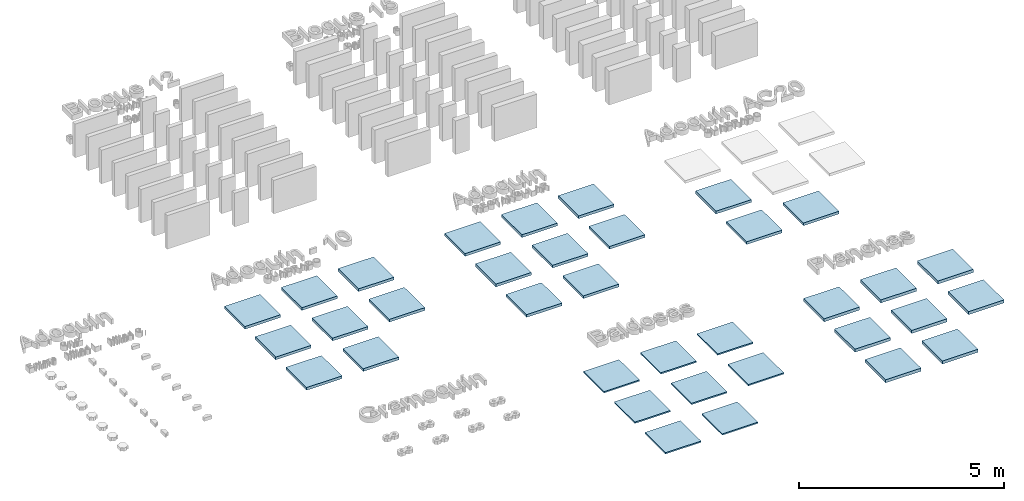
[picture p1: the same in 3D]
Properties of the parts of a building model (IFC2X3), part 2 of 2

# IfcWallStandardCase: Muro básico:Bloque 15 (Solera) / Fachada - Adobe, Muro básico:Bloque 15 (Solera) / Fachada - Adobe:163638
Type - PredefinedType: STANDARD; Material: Bloque - Adobe 0.15 m
Type - Pset_ManufacturerTypeInformation - Manufacturer: Bloques de la Peña
Type - Pset_QuantityTakeOff - Reference: Bloque 15 (Solera) / Fachada - Adobe
Type - Pset_ReinforcementBarPitchOfWall - Reference: Bloque 15 (Solera) / Fachada - Adobe
Type - Pset_WallCommon - IsExternal: no; Reference: Bloque 15 (Solera) / Fachada - Adobe
Pset_QuantityTakeOff - sets with these values: 2
Pset_WallCommon - ExtendToStructure: no; LoadBearing: no

# IfcWallStandardCase: Muro básico:Bloque 15 (Solera) / Fachada - Amarillo, Muro básico:Bloque 15 (Solera) / Fachada - Amarillo:163640
In: Nivel 1
Type - PredefinedType: STANDARD; Material: Bloque - Amarillo 0.15 m
Type - Pset_ManufacturerTypeInformation - Manufacturer: Bloques de la Peña
Type - Pset_QuantityTakeOff - Reference: Bloque 15 (Solera) / Fachada - Amarillo
Type - Pset_ReinforcementBarPitchOfWall - Reference: Bloque 15 (Solera) / Fachada - Amarillo
Type - Pset_WallCommon - IsExternal: no; Reference: Bloque 15 (Solera) / Fachada - Amarillo
Pset_QuantityTakeOff - sets with these values: 2
Pset_WallCommon - ExtendToStructure: no; LoadBearing: no

# IfcWallStandardCase: Muro básico:Bloque 15 (Solera) / Fachada - Chocolate, Muro básico:Bloque 15 (Solera) / Fachada - Chocolate:163644
In: Nivel 1
Type - PredefinedType: STANDARD; Material: Bloque - Chocolate 0.15 m
Type - Pset_ManufacturerTypeInformation - Manufacturer: Bloques de la Peña
Type - Pset_QuantityTakeOff - Reference: Bloque 15 (Solera) / Fachada - Chocolate
Type - Pset_ReinforcementBarPitchOfWall - Reference: Bloque 15 (Solera) / Fachada - Chocolate
Type - Pset_WallCommon - IsExternal: no; Reference: Bloque 15 (Solera) / Fachada - Chocolate
Pset_QuantityTakeOff - sets with these values: 2
Pset_WallCommon - ExtendToStructure: no; LoadBearing: no

# IfcWallStandardCase: Muro básico:Bloque 15 (Solera) / Fachada - Gris, Muro básico:Bloque 15 (Solera) / Fachada - Gris:163642
In: Nivel 1
Type - PredefinedType: STANDARD; Material: Bloque - Gris 0.15 m
Type - Pset_ManufacturerTypeInformation - Manufacturer: Bloques de la Peña
Type - Pset_QuantityTakeOff - Reference: Bloque 15 (Solera) / Fachada - Gris
Type - Pset_ReinforcementBarPitchOfWall - Reference: Bloque 15 (Solera) / Fachada - Gris
Type - Pset_WallCommon - IsExternal: no; Reference: Bloque 15 (Solera) / Fachada - Gris
Pset_QuantityTakeOff - sets with these values: 2
Pset_WallCommon - ExtendToStructure: no; LoadBearing: no

# IfcWallStandardCase: Muro básico:Bloque 15 (Solera) / Fachada - Natural, Muro básico:Bloque 15 (Solera) / Fachada - Natural:163604
In: Nivel 1
Type - PredefinedType: STANDARD; Material: Bloque - Natural 0.15 m
Type - Pset_ManufacturerTypeInformation - Manufacturer: Bloques de la Peña
Type - Pset_QuantityTakeOff - Reference: Bloque 15 (Solera) / Fachada - Natural
Type - Pset_ReinforcementBarPitchOfWall - Reference: Bloque 15 (Solera) / Fachada - Natural
Type - Pset_WallCommon - IsExternal: no; Reference: Bloque 15 (Solera) / Fachada - Natural
Pset_QuantityTakeOff - sets with these values: 2
Pset_WallCommon - ExtendToStructure: no; LoadBearing: no

# IfcWallStandardCase: Muro básico:Bloque 15 (Solera) / Fachada - Negro, Muro básico:Bloque 15 (Solera) / Fachada - Negro:163646
In: Nivel 1
Type - PredefinedType: STANDARD; Material: Bloque - Negro 0.15 m
Type - Pset_ManufacturerTypeInformation - Manufacturer: Bloques de la Peña
Type - Pset_QuantityTakeOff - Reference: Bloque 15 (Solera) / Fachada - Negro
Type - Pset_ReinforcementBarPitchOfWall - Reference: Bloque 15 (Solera) / Fachada - Negro
Type - Pset_WallCommon - IsExternal: no; Reference: Bloque 15 (Solera) / Fachada - Negro
Pset_QuantityTakeOff - sets with these values: 2
Pset_WallCommon - ExtendToStructure: no; LoadBearing: no

# IfcWallStandardCase: Muro básico:Bloque 15 (Solera) / Fachada - Rojo, Muro básico:Bloque 15 (Solera) / Fachada - Rojo:163636
In: Nivel 1
Type - PredefinedType: STANDARD; Material: Bloque - Rojo 0.15 m
Type - Pset_ManufacturerTypeInformation - Manufacturer: Bloques de la Peña
Type - Pset_QuantityTakeOff - Reference: Bloque 15 (Solera) / Fachada - Rojo
Type - Pset_ReinforcementBarPitchOfWall - Reference: Bloque 15 (Solera) / Fachada - Rojo
Type - Pset_WallCommon - IsExternal: no; Reference: Bloque 15 (Solera) / Fachada - Rojo
Pset_QuantityTakeOff - sets with these values: 2
Pset_WallCommon - ExtendToStructure: no; LoadBearing: no

# IfcWallStandardCase: Muro básico:Bloque 15 (Solera) / Fachada - Rosado, Muro básico:Bloque 15 (Solera) / Fachada - Rosado:163634
In: Nivel 1
Type - PredefinedType: STANDARD; Material: Bloque - Rosado 0.15 m
Type - Pset_ManufacturerTypeInformation - Manufacturer: Bloques de la Peña
Type - Pset_QuantityTakeOff - Reference: Bloque 15 (Solera) / Fachada - Rosado
Type - Pset_ReinforcementBarPitchOfWall - Reference: Bloque 15 (Solera) / Fachada - Rosado
Type - Pset_WallCommon - IsExternal: no; Reference: Bloque 15 (Solera) / Fachada - Rosado
Pset_QuantityTakeOff - sets with these values: 2
Pset_WallCommon - ExtendToStructure: no; LoadBearing: no

# IfcWallStandardCase: Muro básico:Bloque 15 / Fachada - Adobe, Muro básico:Bloque 15 / Fachada - Adobe:163610
In: Nivel 1
Type - PredefinedType: STANDARD; Material: Bloque - Adobe 0.15 m
Type - Pset_ManufacturerTypeInformation - Manufacturer: Bloques de la Peña
Type - Pset_QuantityTakeOff - Reference: Bloque 15 / Fachada - Adobe
Type - Pset_ReinforcementBarPitchOfWall - Reference: Bloque 15 / Fachada - Adobe
Type - Pset_WallCommon - IsExternal: no; Reference: Bloque 15 / Fachada - Adobe
Pset_QuantityTakeOff - sets with these values: 2
Pset_WallCommon - ExtendToStructure: no; LoadBearing: no

# IfcWallStandardCase: Muro básico:Bloque 15 / Fachada - Amarillo, Muro básico:Bloque 15 / Fachada - Amarillo:163612
In: Nivel 1
Type - PredefinedType: STANDARD; Material: Bloque - Amarillo 0.15 m
Type - Pset_ManufacturerTypeInformation - Manufacturer: Bloques de la Peña
Type - Pset_QuantityTakeOff - Reference: Bloque 15 / Fachada - Amarillo
Type - Pset_ReinforcementBarPitchOfWall - Reference: Bloque 15 / Fachada - Amarillo
Type - Pset_WallCommon - IsExternal: no; Reference: Bloque 15 / Fachada - Amarillo
Pset_QuantityTakeOff - sets with these values: 2
Pset_WallCommon - ExtendToStructure: no; LoadBearing: no

# IfcWallStandardCase: Muro básico:Bloque 15 / Fachada - Chocolate, Muro básico:Bloque 15 / Fachada - Chocolate:163616
In: Nivel 1
Type - PredefinedType: STANDARD; Material: Bloque - Chocolate 0.15 m
Type - Pset_ManufacturerTypeInformation - Manufacturer: Bloques de la Peña
Type - Pset_QuantityTakeOff - Reference: Bloque 15 / Fachada - Chocolate
Type - Pset_ReinforcementBarPitchOfWall - Reference: Bloque 15 / Fachada - Chocolate
Type - Pset_WallCommon - IsExternal: no; Reference: Bloque 15 / Fachada - Chocolate
Pset_QuantityTakeOff - sets with these values: 2
Pset_WallCommon - ExtendToStructure: no; LoadBearing: no

# IfcWallStandardCase: Muro básico:Bloque 15 / Fachada - Gris, Muro básico:Bloque 15 / Fachada - Gris:163614
In: Nivel 1
Type - PredefinedType: STANDARD; Material: Bloque - Gris 0.15 m
Type - Pset_ManufacturerTypeInformation - Manufacturer: Bloques de la Peña
Type - Pset_QuantityTakeOff - Reference: Bloque 15 / Fachada - Gris
Type - Pset_ReinforcementBarPitchOfWall - Reference: Bloque 15 / Fachada - Gris
Type - Pset_WallCommon - IsExternal: no; Reference: Bloque 15 / Fachada - Gris
Pset_QuantityTakeOff - sets with these values: 2
Pset_WallCommon - ExtendToStructure: no; LoadBearing: no

# IfcWallStandardCase: Muro básico:Bloque 15 / Fachada - Natural, Muro básico:Bloque 15 / Fachada - Natural:163600
In: Nivel 1
Type - PredefinedType: STANDARD; Material: Bloque - Natural 0.15 m
Type - Pset_ManufacturerTypeInformation - Manufacturer: Bloques de la Peña
Type - Pset_QuantityTakeOff - Reference: Bloque 15 / Fachada - Natural
Type - Pset_ReinforcementBarPitchOfWall - Reference: Bloque 15 / Fachada - Natural
Type - Pset_WallCommon - IsExternal: no; Reference: Bloque 15 / Fachada - Natural
Pset_QuantityTakeOff - sets with these values: 2
Pset_WallCommon - ExtendToStructure: no; LoadBearing: no

# IfcWallStandardCase: Muro básico:Bloque 15 / Fachada - Negro, Muro básico:Bloque 15 / Fachada - Negro:163618
In: Nivel 1
Type - PredefinedType: STANDARD; Material: Bloque - Negro 0.15 m
Type - Pset_ManufacturerTypeInformation - Manufacturer: Bloques de la Peña
Type - Pset_QuantityTakeOff - Reference: Bloque 15 / Fachada - Negro
Type - Pset_ReinforcementBarPitchOfWall - Reference: Bloque 15 / Fachada - Negro
Type - Pset_WallCommon - IsExternal: no; Reference: Bloque 15 / Fachada - Negro
Pset_QuantityTakeOff - sets with these values: 2
Pset_WallCommon - ExtendToStructure: no; LoadBearing: no

# IfcWallStandardCase: Muro básico:Bloque 15 / Fachada - Rojo, Muro básico:Bloque 15 / Fachada - Rojo:163608
In: Nivel 1
Type - PredefinedType: STANDARD; Material: Bloque - Rojo 0.15 m
Type - Pset_ManufacturerTypeInformation - Manufacturer: Bloques de la Peña
Type - Pset_QuantityTakeOff - Reference: Bloque 15 / Fachada - Rojo
Type - Pset_ReinforcementBarPitchOfWall - Reference: Bloque 15 / Fachada - Rojo
Type - Pset_WallCommon - IsExternal: no; Reference: Bloque 15 / Fachada - Rojo
Pset_QuantityTakeOff - sets with these values: 2
Pset_WallCommon - ExtendToStructure: no; LoadBearing: no

# IfcWallStandardCase: Muro básico:Bloque 15 / Fachada - Rosado, Muro básico:Bloque 15 / Fachada - Rosado:163606
In: Nivel 1
Type - PredefinedType: STANDARD; Material: Bloque - Rosado 0.15 m
Type - Pset_ManufacturerTypeInformation - Manufacturer: Bloques de la Peña
Type - Pset_QuantityTakeOff - Reference: Bloque 15 / Fachada - Rosado
Type - Pset_ReinforcementBarPitchOfWall - Reference: Bloque 15 / Fachada - Rosado
Type - Pset_WallCommon - IsExternal: no; Reference: Bloque 15 / Fachada - Rosado
Pset_QuantityTakeOff - sets with these values: 2
Pset_WallCommon - ExtendToStructure: no; LoadBearing: no

# IfcWallStandardCase: Muro básico:Bloque 20 (Dado) / Fachada - Adobe, Muro básico:Bloque 20 (Dado) / Fachada - Adobe:163677
In: Nivel 1
Type - PredefinedType: STANDARD; Material: Bloque (Dado) - Adobe 0.2 m
Type - Pset_ManufacturerTypeInformation - Manufacturer: Bloques de la Peña
Type - Pset_QuantityTakeOff - Reference: Bloque 20 (Dado) / Fachada - Adobe
Type - Pset_ReinforcementBarPitchOfWall - Reference: Bloque 20 (Dado) / Fachada - Adobe
Type - Pset_WallCommon - IsExternal: no; Reference: Bloque 20 (Dado) / Fachada - Adobe
Pset_QuantityTakeOff - sets with these values: 2
Pset_WallCommon - ExtendToStructure: no; LoadBearing: no

# IfcWallStandardCase: Muro básico:Bloque 20 (Dado) / Fachada - Amarillo, Muro básico:Bloque 20 (Dado) / Fachada - Amarillo:163679
In: Nivel 1
Type - PredefinedType: STANDARD; Material: Bloque (Dado) - Amarillo 0.2 m
Type - Pset_ManufacturerTypeInformation - Manufacturer: Bloques de la Peña
Type - Pset_QuantityTakeOff - Reference: Bloque 20 (Dado) / Fachada - Amarillo
Type - Pset_ReinforcementBarPitchOfWall - Reference: Bloque 20 (Dado) / Fachada - Amarillo
Type - Pset_WallCommon - IsExternal: no; Reference: Bloque 20 (Dado) / Fachada - Amarillo
Pset_QuantityTakeOff - sets with these values: 2
Pset_WallCommon - ExtendToStructure: no; LoadBearing: no

# IfcWallStandardCase: Muro básico:Bloque 20 (Dado) / Fachada - Chocolate, Muro básico:Bloque 20 (Dado) / Fachada - Chocolate:163683
In: Nivel 1
Type - PredefinedType: STANDARD; Material: Bloque (Dado) - Chocolate 0.2 m
Type - Pset_ManufacturerTypeInformation - Manufacturer: Bloques de la Peña
Type - Pset_QuantityTakeOff - Reference: Bloque 20 (Dado) / Fachada - Chocolate
Type - Pset_ReinforcementBarPitchOfWall - Reference: Bloque 20 (Dado) / Fachada - Chocolate
Type - Pset_WallCommon - IsExternal: no; Reference: Bloque 20 (Dado) / Fachada - Chocolate
Pset_QuantityTakeOff - sets with these values: 2
Pset_WallCommon - ExtendToStructure: no; LoadBearing: no

# IfcWallStandardCase: Muro básico:Bloque 20 (Dado) / Fachada - Gris, Muro básico:Bloque 20 (Dado) / Fachada - Gris:163681
In: Nivel 1
Type - PredefinedType: STANDARD; Material: Bloque (Dado) - Gris 0.2 m
Type - Pset_ManufacturerTypeInformation - Manufacturer: Bloques de la Peña
Type - Pset_QuantityTakeOff - Reference: Bloque 20 (Dado) / Fachada - Gris
Type - Pset_ReinforcementBarPitchOfWall - Reference: Bloque 20 (Dado) / Fachada - Gris
Type - Pset_WallCommon - IsExternal: no; Reference: Bloque 20 (Dado) / Fachada - Gris
Pset_QuantityTakeOff - sets with these values: 2
Pset_WallCommon - ExtendToStructure: no; LoadBearing: no

# IfcWallStandardCase: Muro básico:Bloque 20 (Dado) / Fachada - Natural, Muro básico:Bloque 20 (Dado) / Fachada - Natural:163650
In: Nivel 1
Type - PredefinedType: STANDARD; Material: Bloque (Dado) - Natural 0.2 m
Type - Pset_ManufacturerTypeInformation - Manufacturer: Bloques de la Peña
Type - Pset_QuantityTakeOff - Reference: Bloque 20 (Dado) / Fachada - Natural
Type - Pset_ReinforcementBarPitchOfWall - Reference: Bloque 20 (Dado) / Fachada - Natural
Type - Pset_WallCommon - IsExternal: no; Reference: Bloque 20 (Dado) / Fachada - Natural
Pset_QuantityTakeOff - sets with these values: 2
Pset_WallCommon - ExtendToStructure: no; LoadBearing: no

# IfcWallStandardCase: Muro básico:Bloque 20 (Dado) / Fachada - Negro, Muro básico:Bloque 20 (Dado) / Fachada - Negro:163685
In: Nivel 1
Type - PredefinedType: STANDARD; Material: Bloque (Dado) - Negro 0.2 m
Type - Pset_ManufacturerTypeInformation - Manufacturer: Bloques de la Peña
Type - Pset_QuantityTakeOff - Reference: Bloque 20 (Dado) / Fachada - Negro
Type - Pset_ReinforcementBarPitchOfWall - Reference: Bloque 20 (Dado) / Fachada - Negro
Type - Pset_WallCommon - IsExternal: no; Reference: Bloque 20 (Dado) / Fachada - Negro
Pset_QuantityTakeOff - sets with these values: 2
Pset_WallCommon - ExtendToStructure: no; LoadBearing: no

# IfcWallStandardCase: Muro básico:Bloque 20 (Dado) / Fachada - Rojo, Muro básico:Bloque 20 (Dado) / Fachada - Rojo:163675
In: Nivel 1
Type - PredefinedType: STANDARD; Material: Bloque (Dado) - Rojo 0.2 m
Type - Pset_ManufacturerTypeInformation - Manufacturer: Bloques de la Peña
Type - Pset_QuantityTakeOff - Reference: Bloque 20 (Dado) / Fachada - Rojo
Type - Pset_ReinforcementBarPitchOfWall - Reference: Bloque 20 (Dado) / Fachada - Rojo
Type - Pset_WallCommon - IsExternal: no; Reference: Bloque 20 (Dado) / Fachada - Rojo
Pset_QuantityTakeOff - sets with these values: 2
Pset_WallCommon - ExtendToStructure: no; LoadBearing: no

# IfcWallStandardCase: Muro básico:Bloque 20 (Dado) / Fachada - Rosado, Muro básico:Bloque 20 (Dado) / Fachada - Rosado:163673
In: Nivel 1
Type - PredefinedType: STANDARD; Material: Bloque (Dado) - Rosado 0.2 m
Type - Pset_ManufacturerTypeInformation - Manufacturer: Bloques de la Peña
Type - Pset_QuantityTakeOff - Reference: Bloque 20 (Dado) / Fachada - Rosado
Type - Pset_ReinforcementBarPitchOfWall - Reference: Bloque 20 (Dado) / Fachada - Rosado
Type - Pset_WallCommon - IsExternal: no; Reference: Bloque 20 (Dado) / Fachada - Rosado
Pset_QuantityTakeOff - sets with these values: 2
Pset_WallCommon - ExtendToStructure: no; LoadBearing: no

# IfcWallStandardCase: Muro básico:Bloque 20 (Solera) / Fachada - Adobe, Muro básico:Bloque 20 (Solera) / Fachada - Adobe:163691
In: Nivel 1
Type - PredefinedType: STANDARD; Material: Bloque - Adobe 0.2 m
Type - Pset_ManufacturerTypeInformation - Manufacturer: Bloques de la Peña
Type - Pset_QuantityTakeOff - Reference: Bloque 20 (Solera) / Fachada - Adobe
Type - Pset_ReinforcementBarPitchOfWall - Reference: Bloque 20 (Solera) / Fachada - Adobe
Type - Pset_WallCommon - IsExternal: no; Reference: Bloque 20 (Solera) / Fachada - Adobe
Pset_QuantityTakeOff - sets with these values: 2
Pset_WallCommon - ExtendToStructure: no; LoadBearing: no

# IfcWallStandardCase: Muro básico:Bloque 20 (Solera) / Fachada - Amarillo, Muro básico:Bloque 20 (Solera) / Fachada - Amarillo:163693
In: Nivel 1
Type - PredefinedType: STANDARD; Material: Bloque - Amarillo 0.2 m
Type - Pset_ManufacturerTypeInformation - Manufacturer: Bloques de la Peña
Type - Pset_QuantityTakeOff - Reference: Bloque 20 (Solera) / Fachada - Amarillo
Type - Pset_ReinforcementBarPitchOfWall - Reference: Bloque 20 (Solera) / Fachada - Amarillo
Type - Pset_WallCommon - IsExternal: no; Reference: Bloque 20 (Solera) / Fachada - Amarillo
Pset_QuantityTakeOff - sets with these values: 2
Pset_WallCommon - ExtendToStructure: no; LoadBearing: no

# IfcWallStandardCase: Muro básico:Bloque 20 (Solera) / Fachada - Chocolate, Muro básico:Bloque 20 (Solera) / Fachada - Chocolate:163697
In: Nivel 1
Type - PredefinedType: STANDARD; Material: Bloque - Chocolate 0.2 m
Type - Pset_ManufacturerTypeInformation - Manufacturer: Bloques de la Peña
Type - Pset_QuantityTakeOff - Reference: Bloque 20 (Solera) / Fachada - Chocolate
Type - Pset_ReinforcementBarPitchOfWall - Reference: Bloque 20 (Solera) / Fachada - Chocolate
Type - Pset_WallCommon - IsExternal: no; Reference: Bloque 20 (Solera) / Fachada - Chocolate
Pset_QuantityTakeOff - sets with these values: 2
Pset_WallCommon - ExtendToStructure: no; LoadBearing: no

# IfcWallStandardCase: Muro básico:Bloque 20 (Solera) / Fachada - Gris, Muro básico:Bloque 20 (Solera) / Fachada - Gris:163695
In: Nivel 1
Type - PredefinedType: STANDARD; Material: Bloque - Gris 0.2 m
Type - Pset_ManufacturerTypeInformation - Manufacturer: Bloques de la Peña
Type - Pset_QuantityTakeOff - Reference: Bloque 20 (Solera) / Fachada - Gris
Type - Pset_ReinforcementBarPitchOfWall - Reference: Bloque 20 (Solera) / Fachada - Gris
Type - Pset_WallCommon - IsExternal: no; Reference: Bloque 20 (Solera) / Fachada - Gris
Pset_QuantityTakeOff - sets with these values: 2
Pset_WallCommon - ExtendToStructure: no; LoadBearing: no

# IfcWallStandardCase: Muro básico:Bloque 20 (Solera) / Fachada - Natural, Muro básico:Bloque 20 (Solera) / Fachada - Natural:163655
In: Nivel 1
Type - PredefinedType: STANDARD; Material: Bloque - Natural 0.2 m
Type - Pset_ManufacturerTypeInformation - Manufacturer: Bloques de la Peña
Type - Pset_QuantityTakeOff - Reference: Bloque 20 (Solera) / Fachada - Natural
Type - Pset_ReinforcementBarPitchOfWall - Reference: Bloque 20 (Solera) / Fachada - Natural
Type - Pset_WallCommon - IsExternal: no; Reference: Bloque 20 (Solera) / Fachada - Natural
Pset_QuantityTakeOff - sets with these values: 2
Pset_WallCommon - ExtendToStructure: no; LoadBearing: no

# IfcWallStandardCase: Muro básico:Bloque 20 (Solera) / Fachada - Negro, Muro básico:Bloque 20 (Solera) / Fachada - Negro:163699
In: Nivel 1
Type - PredefinedType: STANDARD; Material: Bloque - Negro 0.2 m
Type - Pset_ManufacturerTypeInformation - Manufacturer: Bloques de la Peña
Type - Pset_QuantityTakeOff - Reference: Bloque 20 (Solera) / Fachada - Negro
Type - Pset_ReinforcementBarPitchOfWall - Reference: Bloque 20 (Solera) / Fachada - Negro
Type - Pset_WallCommon - IsExternal: no; Reference: Bloque 20 (Solera) / Fachada - Negro
Pset_QuantityTakeOff - sets with these values: 2
Pset_WallCommon - ExtendToStructure: no; LoadBearing: no

# IfcWallStandardCase: Muro básico:Bloque 20 (Solera) / Fachada - Rojo, Muro básico:Bloque 20 (Solera) / Fachada - Rojo:163689
In: Nivel 1
Type - PredefinedType: STANDARD; Material: Bloque - Rojo 0.2 m
Type - Pset_ManufacturerTypeInformation - Manufacturer: Bloques de la Peña
Type - Pset_QuantityTakeOff - Reference: Bloque 20 (Solera) / Fachada - Rojo
Type - Pset_ReinforcementBarPitchOfWall - Reference: Bloque 20 (Solera) / Fachada - Rojo
Type - Pset_WallCommon - IsExternal: no; Reference: Bloque 20 (Solera) / Fachada - Rojo
Pset_QuantityTakeOff - sets with these values: 2
Pset_WallCommon - ExtendToStructure: no; LoadBearing: no

# IfcWallStandardCase: Muro básico:Bloque 20 (Solera) / Fachada - Rosado, Muro básico:Bloque 20 (Solera) / Fachada - Rosado:163687
In: Nivel 1
Type - PredefinedType: STANDARD; Material: Bloque - Rosado 0.2 m
Type - Pset_ManufacturerTypeInformation - Manufacturer: Bloques de la Peña
Type - Pset_QuantityTakeOff - Reference: Bloque 20 (Solera) / Fachada - Rosado
Type - Pset_ReinforcementBarPitchOfWall - Reference: Bloque 20 (Solera) / Fachada - Rosado
Type - Pset_WallCommon - IsExternal: no; Reference: Bloque 20 (Solera) / Fachada - Rosado
Pset_QuantityTakeOff - sets with these values: 2
Pset_WallCommon - ExtendToStructure: no; LoadBearing: no

# IfcWallStandardCase: Muro básico:Bloque 20 / Fachada - Adobe, Muro básico:Bloque 20 / Fachada - Adobe:163663
In: Nivel 1
Type - PredefinedType: STANDARD; Material: Bloque - Adobe 0.2 m
Type - Pset_ManufacturerTypeInformation - Manufacturer: Bloques de la Peña
Type - Pset_QuantityTakeOff - Reference: Bloque 20 / Fachada - Adobe
Type - Pset_ReinforcementBarPitchOfWall - Reference: Bloque 20 / Fachada - Adobe
Type - Pset_WallCommon - IsExternal: no; Reference: Bloque 20 / Fachada - Adobe
Pset_QuantityTakeOff - sets with these values: 2
Pset_WallCommon - ExtendToStructure: no; LoadBearing: no

# IfcWallStandardCase: Muro básico:Bloque 20 / Fachada - Amarillo, Muro básico:Bloque 20 / Fachada - Amarillo:163665
In: Nivel 1
Type - PredefinedType: STANDARD; Material: Bloque - Amarillo 0.2 m
Type - Pset_ManufacturerTypeInformation - Manufacturer: Bloques de la Peña
Type - Pset_QuantityTakeOff - Reference: Bloque 20 / Fachada - Amarillo
Type - Pset_ReinforcementBarPitchOfWall - Reference: Bloque 20 / Fachada - Amarillo
Type - Pset_WallCommon - IsExternal: no; Reference: Bloque 20 / Fachada - Amarillo
Pset_QuantityTakeOff - sets with these values: 2
Pset_WallCommon - ExtendToStructure: no; LoadBearing: no

# IfcWallStandardCase: Muro básico:Bloque 20 / Fachada - Chocolate, Muro básico:Bloque 20 / Fachada - Chocolate:163669
In: Nivel 1
Type - PredefinedType: STANDARD; Material: Bloque - Chocolate 0.2 m
Type - Pset_ManufacturerTypeInformation - Manufacturer: Bloques de la Peña
Type - Pset_QuantityTakeOff - Reference: Bloque 20 / Fachada - Chocolate
Type - Pset_ReinforcementBarPitchOfWall - Reference: Bloque 20 / Fachada - Chocolate
Type - Pset_WallCommon - IsExternal: no; Reference: Bloque 20 / Fachada - Chocolate
Pset_QuantityTakeOff - sets with these values: 2
Pset_WallCommon - ExtendToStructure: no; LoadBearing: no

# IfcWallStandardCase: Muro básico:Bloque 20 / Fachada - Gris, Muro básico:Bloque 20 / Fachada - Gris:163667
In: Nivel 1
Type - PredefinedType: STANDARD; Material: Bloque - Gris 0.2 m
Type - Pset_ManufacturerTypeInformation - Manufacturer: Bloques de la Peña
Type - Pset_QuantityTakeOff - Reference: Bloque 20 / Fachada - Gris
Type - Pset_ReinforcementBarPitchOfWall - Reference: Bloque 20 / Fachada - Gris
Type - Pset_WallCommon - IsExternal: no; Reference: Bloque 20 / Fachada - Gris
Pset_QuantityTakeOff - sets with these values: 2
Pset_WallCommon - ExtendToStructure: no; LoadBearing: no

# IfcWallStandardCase: Muro básico:Bloque 20 / Fachada - Natural, Muro básico:Bloque 20 / Fachada - Natural:163648
In: Nivel 1
Type - PredefinedType: STANDARD; Material: Bloque - Natural 0.2 m
Type - Pset_ManufacturerTypeInformation - Manufacturer: Bloques de la Peña
Type - Pset_QuantityTakeOff - Reference: Bloque 20 / Fachada - Natural
Type - Pset_ReinforcementBarPitchOfWall - Reference: Bloque 20 / Fachada - Natural
Type - Pset_WallCommon - IsExternal: no; Reference: Bloque 20 / Fachada - Natural
Pset_QuantityTakeOff - sets with these values: 2
Pset_WallCommon - ExtendToStructure: no; LoadBearing: no

# IfcWallStandardCase: Muro básico:Bloque 20 / Fachada - Negro, Muro básico:Bloque 20 / Fachada - Negro:163671
In: Nivel 1
Type - PredefinedType: STANDARD; Material: Bloque - Negro 0.2 m
Type - Pset_ManufacturerTypeInformation - Manufacturer: Bloques de la Peña
Type - Pset_QuantityTakeOff - Reference: Bloque 20 / Fachada - Negro
Type - Pset_ReinforcementBarPitchOfWall - Reference: Bloque 20 / Fachada - Negro
Type - Pset_WallCommon - IsExternal: no; Reference: Bloque 20 / Fachada - Negro
Pset_QuantityTakeOff - sets with these values: 2
Pset_WallCommon - ExtendToStructure: no; LoadBearing: no

# IfcWallStandardCase: Muro básico:Bloque 20 / Fachada - Rojo, Muro básico:Bloque 20 / Fachada - Rojo:163661
In: Nivel 1
Type - PredefinedType: STANDARD; Material: Bloque - Rojo 0.2 m
Type - Pset_ManufacturerTypeInformation - Manufacturer: Bloques de la Peña
Type - Pset_QuantityTakeOff - Reference: Bloque 20 / Fachada - Rojo
Type - Pset_ReinforcementBarPitchOfWall - Reference: Bloque 20 / Fachada - Rojo
Type - Pset_WallCommon - IsExternal: no; Reference: Bloque 20 / Fachada - Rojo
Pset_QuantityTakeOff - sets with these values: 2
Pset_WallCommon - ExtendToStructure: no; LoadBearing: no

# IfcWallStandardCase: Muro básico:Bloque 20 / Fachada - Rosado, Muro básico:Bloque 20 / Fachada - Rosado:163659
In: Nivel 1
Type - PredefinedType: STANDARD; Material: Bloque - Rosado 0.2 m
Type - Pset_ManufacturerTypeInformation - Manufacturer: Bloques de la Peña
Type - Pset_QuantityTakeOff - Reference: Bloque 20 / Fachada - Rosado
Type - Pset_ReinforcementBarPitchOfWall - Reference: Bloque 20 / Fachada - Rosado
Type - Pset_WallCommon - IsExternal: no; Reference: Bloque 20 / Fachada - Rosado
Pset_QuantityTakeOff - sets with these values: 2
Pset_WallCommon - ExtendToStructure: no; LoadBearing: no
